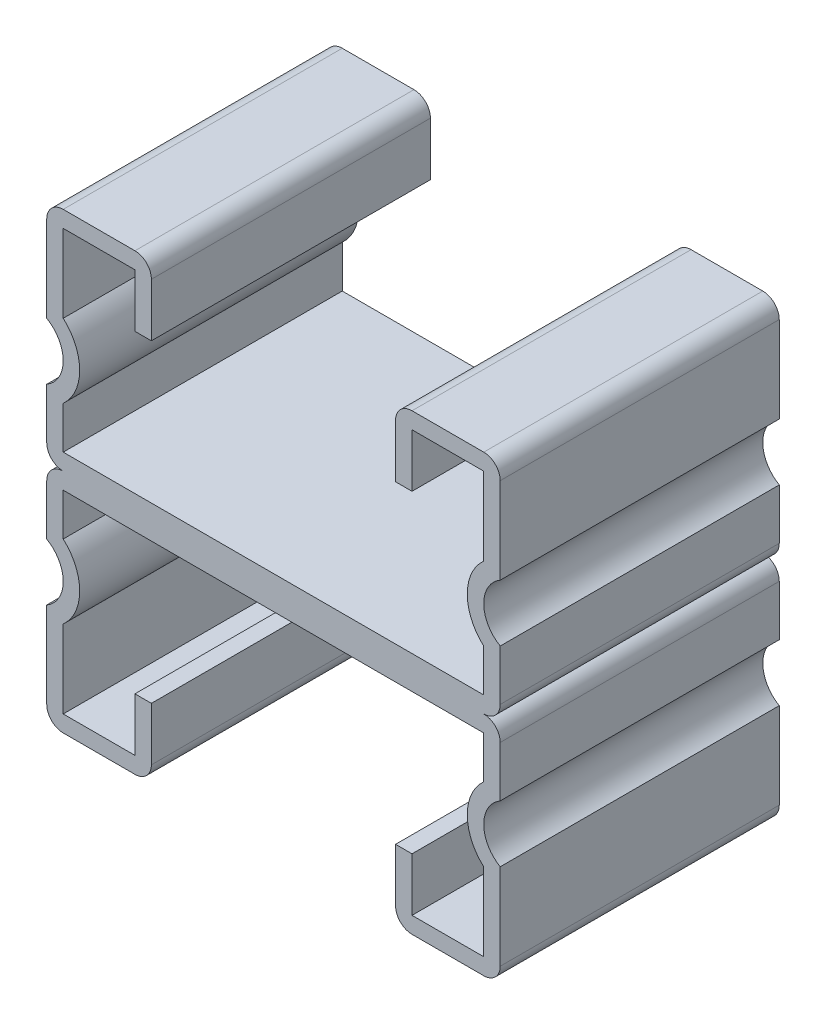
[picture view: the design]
ISO-10303-21;
HEADER;
FILE_DESCRIPTION(('STEP AP214'),'2;1');
FILE_NAME('part.step','',(''),(''),'','','');
FILE_SCHEMA(('AUTOMOTIVE_DESIGN { 1 0 10303 214 1 1 1 1 }'));
ENDSEC;
DATA;
#1=APPLICATION_CONTEXT('core data for automotive mechanical design processes');
#2=APPLICATION_PROTOCOL_DEFINITION('international standard','automotive_design',2000,#1);
#3=PRODUCT_CONTEXT('',#1,'mechanical');
#4=PRODUCT('Part','Part','',(#3));
#5=PRODUCT_RELATED_PRODUCT_CATEGORY('part','',(#4));
#6=PRODUCT_DEFINITION_FORMATION('','',#4);
#7=PRODUCT_DEFINITION_CONTEXT('part definition',#1,'design');
#8=PRODUCT_DEFINITION('design','',#6,#7);
#9=PRODUCT_DEFINITION_SHAPE('','',#8);
#10=(LENGTH_UNIT() NAMED_UNIT(*) SI_UNIT(.MILLI.,.METRE.));
#11=(NAMED_UNIT(*) PLANE_ANGLE_UNIT() SI_UNIT($,.RADIAN.));
#12=(NAMED_UNIT(*) SI_UNIT($,.STERADIAN.) SOLID_ANGLE_UNIT());
#13=UNCERTAINTY_MEASURE_WITH_UNIT(LENGTH_MEASURE(1.E-05),#10,'distance_accuracy_value','');
#14=(GEOMETRIC_REPRESENTATION_CONTEXT(3) GLOBAL_UNCERTAINTY_ASSIGNED_CONTEXT((#13)) GLOBAL_UNIT_ASSIGNED_CONTEXT((#10,
#11,#12)) REPRESENTATION_CONTEXT('',''));
#15=CARTESIAN_POINT('',(0.,0.,0.));
#16=DIRECTION('',(0.,0.,1.));
#17=DIRECTION('',(1.,0.,0.));
#18=AXIS2_PLACEMENT_3D('',#15,#16,#17);
#19=CARTESIAN_POINT('',(-19.1389,19.1389,12.7));
#20=DIRECTION('',(-1.,0.,0.));
#21=DIRECTION('',(0.,0.,1.));
#22=AXIS2_PLACEMENT_3D('',#19,#20,#21);
#23=PLANE('',#22);
#24=DIRECTION('',(0.,1.,0.));
#25=VECTOR('',#24,1.);
#26=CARTESIAN_POINT('',(-19.1389,19.1389,-12.7));
#27=LINE('',#26,#25);
#28=CARTESIAN_POINT('',(-19.1389,12.0504714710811,-12.7));
#29=VERTEX_POINT('',#28);
#30=CARTESIAN_POINT('',(-19.1389,19.1389,-12.7));
#31=VERTEX_POINT('',#30);
#32=EDGE_CURVE('E261',#29,#31,#27,.T.);
#33=ORIENTED_EDGE('',*,*,#32,.T.);
#34=DIRECTION('',(0.,0.,-1.));
#35=VECTOR('',#34,1.);
#36=CARTESIAN_POINT('',(-19.1389,19.1389,12.7));
#37=LINE('',#36,#35);
#38=CARTESIAN_POINT('',(-19.1389,19.1389,12.7));
#39=VERTEX_POINT('',#38);
#40=EDGE_CURVE('E11',#39,#31,#37,.T.);
#41=ORIENTED_EDGE('',*,*,#40,.F.);
#42=DIRECTION('',(0.,1.,0.));
#43=VECTOR('',#42,1.);
#44=CARTESIAN_POINT('',(-19.1389,19.1389,12.7));
#45=LINE('',#44,#43);
#46=CARTESIAN_POINT('',(-19.1389,12.0504714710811,12.7));
#47=VERTEX_POINT('',#46);
#48=EDGE_CURVE('E318',#47,#39,#45,.T.);
#49=ORIENTED_EDGE('',*,*,#48,.F.);
#50=DIRECTION('',(0.,0.,-1.));
#51=VECTOR('',#50,1.);
#52=CARTESIAN_POINT('',(-19.1389,12.0504714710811,12.7));
#53=LINE('',#52,#51);
#54=EDGE_CURVE('E257',#47,#29,#53,.T.);
#55=ORIENTED_EDGE('',*,*,#54,.T.);
#56=EDGE_LOOP('',(#33,#41,#49,#55));
#57=FACE_BOUND('',#56,.T.);
#58=ADVANCED_FACE('F32',(#57),#23,.F.);
#59=CARTESIAN_POINT('',(-19.1389,19.1389,12.7));
#60=DIRECTION('',(0.,1.,0.));
#61=DIRECTION('',(0.,0.,1.));
#62=AXIS2_PLACEMENT_3D('',#59,#60,#61);
#63=PLANE('',#62);
#64=DIRECTION('',(1.,0.,0.));
#65=VECTOR('',#64,1.);
#66=CARTESIAN_POINT('',(-19.1389,19.1389,-12.7));
#67=LINE('',#66,#65);
#68=CARTESIAN_POINT('',(-12.6111,19.1389,-12.7));
#69=VERTEX_POINT('',#68);
#70=EDGE_CURVE('E264',#31,#69,#67,.T.);
#71=ORIENTED_EDGE('',*,*,#70,.T.);
#72=DIRECTION('',(0.,0.,-1.));
#73=VECTOR('',#72,1.);
#74=CARTESIAN_POINT('',(-12.6111,19.1389,12.7));
#75=LINE('',#74,#73);
#76=CARTESIAN_POINT('',(-12.6111,19.1389,12.7));
#77=VERTEX_POINT('',#76);
#78=EDGE_CURVE('E40',#77,#69,#75,.T.);
#79=ORIENTED_EDGE('',*,*,#78,.F.);
#80=DIRECTION('',(1.,0.,0.));
#81=VECTOR('',#80,1.);
#82=CARTESIAN_POINT('',(-19.1389,19.1389,12.7));
#83=LINE('',#82,#81);
#84=EDGE_CURVE('E155',#39,#77,#83,.T.);
#85=ORIENTED_EDGE('',*,*,#84,.F.);
#86=ORIENTED_EDGE('',*,*,#40,.T.);
#87=EDGE_LOOP('',(#71,#79,#85,#86));
#88=FACE_BOUND('',#87,.T.);
#89=ADVANCED_FACE('F484',(#88),#63,.F.);
#90=CARTESIAN_POINT('',(-12.6111,19.1389,12.7));
#91=DIRECTION('',(1.,0.,0.));
#92=DIRECTION('',(0.,1.,0.));
#93=AXIS2_PLACEMENT_3D('',#90,#91,#92);
#94=PLANE('',#93);
#95=DIRECTION('',(0.,-1.,0.));
#96=VECTOR('',#95,1.);
#97=CARTESIAN_POINT('',(-12.6111,19.1389,-12.7));
#98=LINE('',#97,#96);
#99=CARTESIAN_POINT('',(-12.6111,14.2875,-12.7));
#100=VERTEX_POINT('',#99);
#101=EDGE_CURVE('E267',#69,#100,#98,.T.);
#102=ORIENTED_EDGE('',*,*,#101,.T.);
#103=DIRECTION('',(0.,0.,-1.));
#104=VECTOR('',#103,1.);
#105=CARTESIAN_POINT('',(-12.6111,14.2875,12.7));
#106=LINE('',#105,#104);
#107=CARTESIAN_POINT('',(-12.6111,14.2875,12.7));
#108=VERTEX_POINT('',#107);
#109=EDGE_CURVE('E391',#108,#100,#106,.T.);
#110=ORIENTED_EDGE('',*,*,#109,.F.);
#111=DIRECTION('',(0.,-1.,0.));
#112=VECTOR('',#111,1.);
#113=CARTESIAN_POINT('',(-12.6111,19.1389,12.7));
#114=LINE('',#113,#112);
#115=EDGE_CURVE('E399',#77,#108,#114,.T.);
#116=ORIENTED_EDGE('',*,*,#115,.F.);
#117=ORIENTED_EDGE('',*,*,#78,.T.);
#118=EDGE_LOOP('',(#102,#110,#116,#117));
#119=FACE_BOUND('',#118,.T.);
#120=ADVANCED_FACE('F397',(#119),#94,.F.);
#121=CARTESIAN_POINT('',(-12.6111,14.2875,12.7));
#122=DIRECTION('',(0.,1.,0.));
#123=DIRECTION('',(0.,0.,1.));
#124=AXIS2_PLACEMENT_3D('',#121,#122,#123);
#125=PLANE('',#124);
#126=DIRECTION('',(1.,0.,0.));
#127=VECTOR('',#126,1.);
#128=CARTESIAN_POINT('',(-12.6111,14.2875,-12.7));
#129=LINE('',#128,#127);
#130=CARTESIAN_POINT('',(-11.1125,14.2875,-12.7));
#131=VERTEX_POINT('',#130);
#132=EDGE_CURVE('E269',#100,#131,#129,.T.);
#133=ORIENTED_EDGE('',*,*,#132,.T.);
#134=DIRECTION('',(0.,0.,-1.));
#135=VECTOR('',#134,1.);
#136=CARTESIAN_POINT('',(-11.1125,14.2875,12.7));
#137=LINE('',#136,#135);
#138=CARTESIAN_POINT('',(-11.1125,14.2875,12.7));
#139=VERTEX_POINT('',#138);
#140=EDGE_CURVE('E388',#139,#131,#137,.T.);
#141=ORIENTED_EDGE('',*,*,#140,.F.);
#142=DIRECTION('',(1.,0.,0.));
#143=VECTOR('',#142,1.);
#144=CARTESIAN_POINT('',(-12.6111,14.2875,12.7));
#145=LINE('',#144,#143);
#146=EDGE_CURVE('E417',#108,#139,#145,.T.);
#147=ORIENTED_EDGE('',*,*,#146,.F.);
#148=ORIENTED_EDGE('',*,*,#109,.T.);
#149=EDGE_LOOP('',(#133,#141,#147,#148));
#150=FACE_BOUND('',#149,.T.);
#151=ADVANCED_FACE('F408',(#150),#125,.F.);
#152=CARTESIAN_POINT('',(-11.1125,19.1389,12.7));
#153=DIRECTION('',(-1.,0.,0.));
#154=DIRECTION('',(0.,-1.,0.));
#155=AXIS2_PLACEMENT_3D('',#152,#153,#154);
#156=PLANE('',#155);
#157=DIRECTION('',(0.,1.,0.));
#158=VECTOR('',#157,1.);
#159=CARTESIAN_POINT('',(-11.1125,19.1389,-12.7));
#160=LINE('',#159,#158);
#161=CARTESIAN_POINT('',(-11.1125,19.1389,-12.7));
#162=VERTEX_POINT('',#161);
#163=EDGE_CURVE('E271',#131,#162,#160,.T.);
#164=ORIENTED_EDGE('',*,*,#163,.T.);
#165=DIRECTION('',(0.,0.,-1.));
#166=VECTOR('',#165,1.);
#167=CARTESIAN_POINT('',(-11.1125,19.1389,12.7));
#168=LINE('',#167,#166);
#169=CARTESIAN_POINT('',(-11.1125,19.1389,12.7));
#170=VERTEX_POINT('',#169);
#171=EDGE_CURVE('E385',#170,#162,#168,.T.);
#172=ORIENTED_EDGE('',*,*,#171,.F.);
#173=DIRECTION('',(0.,1.,0.));
#174=VECTOR('',#173,1.);
#175=CARTESIAN_POINT('',(-11.1125,19.1389,12.7));
#176=LINE('',#175,#174);
#177=EDGE_CURVE('E414',#139,#170,#176,.T.);
#178=ORIENTED_EDGE('',*,*,#177,.F.);
#179=ORIENTED_EDGE('',*,*,#140,.T.);
#180=EDGE_LOOP('',(#164,#172,#178,#179));
#181=FACE_BOUND('',#180,.T.);
#182=ADVANCED_FACE('F412',(#181),#156,.F.);
#183=CARTESIAN_POINT('',(-12.6111,19.1389,12.7));
#184=DIRECTION('',(0.,0.,-1.));
#185=DIRECTION('',(-1.,0.,0.));
#186=AXIS2_PLACEMENT_3D('',#183,#184,#185);
#187=CYLINDRICAL_SURFACE('',#186,1.4986);
#188=CARTESIAN_POINT('',(-12.6111,19.1389,-12.7));
#189=DIRECTION('',(0.,0.,1.));
#190=DIRECTION('',(-1.,0.,0.));
#191=AXIS2_PLACEMENT_3D('',#188,#189,#190);
#192=CIRCLE('',#191,1.4986);
#193=CARTESIAN_POINT('',(-12.6111,20.6375,-12.7));
#194=VERTEX_POINT('',#193);
#195=EDGE_CURVE('E273',#162,#194,#192,.T.);
#196=ORIENTED_EDGE('',*,*,#195,.T.);
#197=DIRECTION('',(0.,0.,-1.));
#198=VECTOR('',#197,1.);
#199=CARTESIAN_POINT('',(-12.6111,20.6375,12.7));
#200=LINE('',#199,#198);
#201=CARTESIAN_POINT('',(-12.6111,20.6375,12.7));
#202=VERTEX_POINT('',#201);
#203=EDGE_CURVE('E382',#202,#194,#200,.T.);
#204=ORIENTED_EDGE('',*,*,#203,.F.);
#205=CARTESIAN_POINT('',(-12.6111,19.1389,12.7));
#206=DIRECTION('',(0.,0.,1.));
#207=DIRECTION('',(-1.,0.,0.));
#208=AXIS2_PLACEMENT_3D('',#205,#206,#207);
#209=CIRCLE('',#208,1.4986);
#210=EDGE_CURVE('E416',#170,#202,#209,.T.);
#211=ORIENTED_EDGE('',*,*,#210,.F.);
#212=ORIENTED_EDGE('',*,*,#171,.T.);
#213=EDGE_LOOP('',(#196,#204,#211,#212));
#214=FACE_BOUND('',#213,.T.);
#215=ADVANCED_FACE('F497',(#214),#187,.T.);
#216=CARTESIAN_POINT('',(-19.1389,20.6375,12.7));
#217=DIRECTION('',(0.,-1.,0.));
#218=DIRECTION('',(0.,0.,-1.));
#219=AXIS2_PLACEMENT_3D('',#216,#217,#218);
#220=PLANE('',#219);
#221=DIRECTION('',(-1.,0.,0.));
#222=VECTOR('',#221,1.);
#223=CARTESIAN_POINT('',(-19.1389,20.6375,-12.7));
#224=LINE('',#223,#222);
#225=CARTESIAN_POINT('',(-19.1389,20.6375,-12.7));
#226=VERTEX_POINT('',#225);
#227=EDGE_CURVE('E275',#194,#226,#224,.T.);
#228=ORIENTED_EDGE('',*,*,#227,.T.);
#229=DIRECTION('',(0.,0.,-1.));
#230=VECTOR('',#229,1.);
#231=CARTESIAN_POINT('',(-19.1389,20.6375,12.7));
#232=LINE('',#231,#230);
#233=CARTESIAN_POINT('',(-19.1389,20.6375,12.7));
#234=VERTEX_POINT('',#233);
#235=EDGE_CURVE('E379',#234,#226,#232,.T.);
#236=ORIENTED_EDGE('',*,*,#235,.F.);
#237=DIRECTION('',(-1.,0.,0.));
#238=VECTOR('',#237,1.);
#239=CARTESIAN_POINT('',(-19.1389,20.6375,12.7));
#240=LINE('',#239,#238);
#241=EDGE_CURVE('E419',#202,#234,#240,.T.);
#242=ORIENTED_EDGE('',*,*,#241,.F.);
#243=ORIENTED_EDGE('',*,*,#203,.T.);
#244=EDGE_LOOP('',(#228,#236,#242,#243));
#245=FACE_BOUND('',#244,.T.);
#246=ADVANCED_FACE('F500',(#245),#220,.F.);
#247=CARTESIAN_POINT('',(-19.1389,19.1389,12.7));
#248=DIRECTION('',(0.,0.,-1.));
#249=DIRECTION('',(-1.,0.,0.));
#250=AXIS2_PLACEMENT_3D('',#247,#248,#249);
#251=CYLINDRICAL_SURFACE('',#250,1.4986);
#252=CARTESIAN_POINT('',(-19.1389,19.1389,-12.7));
#253=DIRECTION('',(0.,0.,1.));
#254=DIRECTION('',(-1.,0.,0.));
#255=AXIS2_PLACEMENT_3D('',#252,#253,#254);
#256=CIRCLE('',#255,1.4986);
#257=CARTESIAN_POINT('',(-20.6375,19.1389,-12.7));
#258=VERTEX_POINT('',#257);
#259=EDGE_CURVE('E277',#226,#258,#256,.T.);
#260=ORIENTED_EDGE('',*,*,#259,.T.);
#261=DIRECTION('',(0.,0.,-1.));
#262=VECTOR('',#261,1.);
#263=CARTESIAN_POINT('',(-20.6375,19.1389,12.7));
#264=LINE('',#263,#262);
#265=CARTESIAN_POINT('',(-20.6375,19.1389,12.7));
#266=VERTEX_POINT('',#265);
#267=EDGE_CURVE('E376',#266,#258,#264,.T.);
#268=ORIENTED_EDGE('',*,*,#267,.F.);
#269=CARTESIAN_POINT('',(-19.1389,19.1389,12.7));
#270=DIRECTION('',(0.,0.,1.));
#271=DIRECTION('',(-1.,0.,0.));
#272=AXIS2_PLACEMENT_3D('',#269,#270,#271);
#273=CIRCLE('',#272,1.4986);
#274=EDGE_CURVE('E425',#234,#266,#273,.T.);
#275=ORIENTED_EDGE('',*,*,#274,.F.);
#276=ORIENTED_EDGE('',*,*,#235,.T.);
#277=EDGE_LOOP('',(#260,#268,#275,#276));
#278=FACE_BOUND('',#277,.T.);
#279=ADVANCED_FACE('F504',(#278),#251,.T.);
#280=CARTESIAN_POINT('',(-20.6375,19.1389,12.7));
#281=DIRECTION('',(1.,0.,0.));
#282=DIRECTION('',(0.,1.,0.));
#283=AXIS2_PLACEMENT_3D('',#280,#281,#282);
#284=PLANE('',#283);
#285=DIRECTION('',(0.,-1.,0.));
#286=VECTOR('',#285,1.);
#287=CARTESIAN_POINT('',(-20.6375,19.1389,-12.7));
#288=LINE('',#287,#286);
#289=CARTESIAN_POINT('',(-20.6375,11.2951513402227,-12.7));
#290=VERTEX_POINT('',#289);
#291=EDGE_CURVE('E279',#258,#290,#288,.T.);
#292=ORIENTED_EDGE('',*,*,#291,.T.);
#293=DIRECTION('',(0.,0.,-1.));
#294=VECTOR('',#293,1.);
#295=CARTESIAN_POINT('',(-20.6375,11.2951513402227,12.7));
#296=LINE('',#295,#294);
#297=CARTESIAN_POINT('',(-20.6375,11.2951513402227,12.7));
#298=VERTEX_POINT('',#297);
#299=EDGE_CURVE('E373',#298,#290,#296,.T.);
#300=ORIENTED_EDGE('',*,*,#299,.F.);
#301=DIRECTION('',(0.,-1.,0.));
#302=VECTOR('',#301,1.);
#303=CARTESIAN_POINT('',(-20.6375,19.1389,12.7));
#304=LINE('',#303,#302);
#305=EDGE_CURVE('E427',#266,#298,#304,.T.);
#306=ORIENTED_EDGE('',*,*,#305,.F.);
#307=ORIENTED_EDGE('',*,*,#267,.T.);
#308=EDGE_LOOP('',(#292,#300,#306,#307));
#309=FACE_BOUND('',#308,.T.);
#310=ADVANCED_FACE('F508',(#309),#284,.F.);
#311=CARTESIAN_POINT('',(-22.1361,8.69949999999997,12.7));
#312=DIRECTION('',(0.,0.,-1.));
#313=DIRECTION('',(-1.,0.,0.));
#314=AXIS2_PLACEMENT_3D('',#311,#312,#313);
#315=CYLINDRICAL_SURFACE('',#314,2.9972);
#316=CARTESIAN_POINT('',(-22.1361,8.69949999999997,-12.7));
#317=DIRECTION('',(0.,0.,-1.));
#318=DIRECTION('',(1.,0.,0.));
#319=AXIS2_PLACEMENT_3D('',#316,#317,#318);
#320=CIRCLE('',#319,2.9972);
#321=CARTESIAN_POINT('',(-20.6375,6.10384865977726,-12.7));
#322=VERTEX_POINT('',#321);
#323=EDGE_CURVE('E281',#290,#322,#320,.T.);
#324=ORIENTED_EDGE('',*,*,#323,.T.);
#325=DIRECTION('',(0.,0.,-1.));
#326=VECTOR('',#325,1.);
#327=CARTESIAN_POINT('',(-20.6375,6.10384865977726,12.7));
#328=LINE('',#327,#326);
#329=CARTESIAN_POINT('',(-20.6375,6.10384865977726,12.7));
#330=VERTEX_POINT('',#329);
#331=EDGE_CURVE('E370',#330,#322,#328,.T.);
#332=ORIENTED_EDGE('',*,*,#331,.F.);
#333=CARTESIAN_POINT('',(-22.1361,8.69949999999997,12.7));
#334=DIRECTION('',(0.,0.,-1.));
#335=DIRECTION('',(1.,0.,0.));
#336=AXIS2_PLACEMENT_3D('',#333,#334,#335);
#337=CIRCLE('',#336,2.9972);
#338=EDGE_CURVE('E429',#298,#330,#337,.T.);
#339=ORIENTED_EDGE('',*,*,#338,.F.);
#340=ORIENTED_EDGE('',*,*,#299,.T.);
#341=EDGE_LOOP('',(#324,#332,#339,#340));
#342=FACE_BOUND('',#341,.T.);
#343=ADVANCED_FACE('F512',(#342),#315,.F.);
#344=CARTESIAN_POINT('',(-20.6375,6.10384865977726,12.7));
#345=DIRECTION('',(1.,0.,0.));
#346=DIRECTION('',(0.,0.,-1.));
#347=AXIS2_PLACEMENT_3D('',#344,#345,#346);
#348=PLANE('',#347);
#349=DIRECTION('',(0.,-1.,0.));
#350=VECTOR('',#349,1.);
#351=CARTESIAN_POINT('',(-20.6375,6.10384865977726,-12.7));
#352=LINE('',#351,#350);
#353=CARTESIAN_POINT('',(-20.6375,1.4986,-12.7));
#354=VERTEX_POINT('',#353);
#355=EDGE_CURVE('E283',#322,#354,#352,.T.);
#356=ORIENTED_EDGE('',*,*,#355,.T.);
#357=DIRECTION('',(0.,0.,-1.));
#358=VECTOR('',#357,1.);
#359=CARTESIAN_POINT('',(-20.6375,1.4986,12.7));
#360=LINE('',#359,#358);
#361=CARTESIAN_POINT('',(-20.6375,1.4986,12.7));
#362=VERTEX_POINT('',#361);
#363=EDGE_CURVE('E367',#362,#354,#360,.T.);
#364=ORIENTED_EDGE('',*,*,#363,.F.);
#365=DIRECTION('',(0.,-1.,0.));
#366=VECTOR('',#365,1.);
#367=CARTESIAN_POINT('',(-20.6375,6.10384865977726,12.7));
#368=LINE('',#367,#366);
#369=EDGE_CURVE('E431',#330,#362,#368,.T.);
#370=ORIENTED_EDGE('',*,*,#369,.F.);
#371=ORIENTED_EDGE('',*,*,#331,.T.);
#372=EDGE_LOOP('',(#356,#364,#370,#371));
#373=FACE_BOUND('',#372,.T.);
#374=ADVANCED_FACE('F516',(#373),#348,.F.);
#375=CARTESIAN_POINT('',(-19.1389,1.4986,12.7));
#376=DIRECTION('',(0.,0.,-1.));
#377=DIRECTION('',(-1.,0.,0.));
#378=AXIS2_PLACEMENT_3D('',#375,#376,#377);
#379=CYLINDRICAL_SURFACE('',#378,1.4986);
#380=CARTESIAN_POINT('',(-19.1389,1.4986,-12.7));
#381=DIRECTION('',(0.,0.,1.));
#382=DIRECTION('',(-1.,0.,0.));
#383=AXIS2_PLACEMENT_3D('',#380,#381,#382);
#384=CIRCLE('',#383,1.4986);
#385=CARTESIAN_POINT('',(-19.1389,0.,-12.7));
#386=VERTEX_POINT('',#385);
#387=EDGE_CURVE('E285',#354,#386,#384,.T.);
#388=ORIENTED_EDGE('',*,*,#387,.T.);
#389=DIRECTION('',(0.,0.,-1.));
#390=VECTOR('',#389,1.);
#391=CARTESIAN_POINT('',(-19.1389,0.,12.7));
#392=LINE('',#391,#390);
#393=CARTESIAN_POINT('',(-19.1389,0.,12.7));
#394=VERTEX_POINT('',#393);
#395=EDGE_CURVE('E364',#394,#386,#392,.T.);
#396=ORIENTED_EDGE('',*,*,#395,.F.);
#397=CARTESIAN_POINT('',(-19.1389,1.4986,12.7));
#398=DIRECTION('',(0.,0.,1.));
#399=DIRECTION('',(-1.,0.,0.));
#400=AXIS2_PLACEMENT_3D('',#397,#398,#399);
#401=CIRCLE('',#400,1.4986);
#402=EDGE_CURVE('E433',#362,#394,#401,.T.);
#403=ORIENTED_EDGE('',*,*,#402,.F.);
#404=ORIENTED_EDGE('',*,*,#363,.T.);
#405=EDGE_LOOP('',(#388,#396,#403,#404));
#406=FACE_BOUND('',#405,.T.);
#407=ADVANCED_FACE('F520',(#406),#379,.T.);
#408=CARTESIAN_POINT('',(19.1389,1.49860000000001,12.7));
#409=DIRECTION('',(0.,0.,-1.));
#410=DIRECTION('',(-1.,0.,0.));
#411=AXIS2_PLACEMENT_3D('',#408,#409,#410);
#412=CYLINDRICAL_SURFACE('',#411,1.4986);
#413=CARTESIAN_POINT('',(19.1389,1.49860000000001,-12.7));
#414=DIRECTION('',(0.,0.,1.));
#415=DIRECTION('',(-1.,0.,0.));
#416=AXIS2_PLACEMENT_3D('',#413,#414,#415);
#417=CIRCLE('',#416,1.4986);
#418=CARTESIAN_POINT('',(19.1389,0.,-12.7));
#419=VERTEX_POINT('',#418);
#420=CARTESIAN_POINT('',(20.6375,1.49860000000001,-12.7));
#421=VERTEX_POINT('',#420);
#422=EDGE_CURVE('E287',#419,#421,#417,.T.);
#423=ORIENTED_EDGE('',*,*,#422,.T.);
#424=DIRECTION('',(0.,0.,-1.));
#425=VECTOR('',#424,1.);
#426=CARTESIAN_POINT('',(20.6375,1.49860000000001,12.7));
#427=LINE('',#426,#425);
#428=CARTESIAN_POINT('',(20.6375,1.49860000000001,12.7));
#429=VERTEX_POINT('',#428);
#430=EDGE_CURVE('E358',#429,#421,#427,.T.);
#431=ORIENTED_EDGE('',*,*,#430,.F.);
#432=CARTESIAN_POINT('',(19.1389,1.49860000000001,12.7));
#433=DIRECTION('',(0.,0.,1.));
#434=DIRECTION('',(-1.,0.,0.));
#435=AXIS2_PLACEMENT_3D('',#432,#433,#434);
#436=CIRCLE('',#435,1.4986);
#437=CARTESIAN_POINT('',(19.1389,0.,12.7));
#438=VERTEX_POINT('',#437);
#439=EDGE_CURVE('E435',#438,#429,#436,.T.);
#440=ORIENTED_EDGE('',*,*,#439,.F.);
#441=DIRECTION('',(0.,0.,-1.));
#442=VECTOR('',#441,1.);
#443=CARTESIAN_POINT('',(19.1389,0.,12.7));
#444=LINE('',#443,#442);
#445=EDGE_CURVE('E361',#438,#419,#444,.T.);
#446=ORIENTED_EDGE('',*,*,#445,.T.);
#447=EDGE_LOOP('',(#423,#431,#440,#446));
#448=FACE_BOUND('',#447,.T.);
#449=ADVANCED_FACE('F524',(#448),#412,.T.);
#450=CARTESIAN_POINT('',(20.6375,1.49860000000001,12.7));
#451=DIRECTION('',(-1.,0.,0.));
#452=DIRECTION('',(0.,0.,1.));
#453=AXIS2_PLACEMENT_3D('',#450,#451,#452);
#454=PLANE('',#453);
#455=DIRECTION('',(0.,1.,0.));
#456=VECTOR('',#455,1.);
#457=CARTESIAN_POINT('',(20.6375,1.49860000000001,-12.7));
#458=LINE('',#457,#456);
#459=CARTESIAN_POINT('',(20.6375,6.10384865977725,-12.7));
#460=VERTEX_POINT('',#459);
#461=EDGE_CURVE('E289',#421,#460,#458,.T.);
#462=ORIENTED_EDGE('',*,*,#461,.T.);
#463=DIRECTION('',(0.,0.,-1.));
#464=VECTOR('',#463,1.);
#465=CARTESIAN_POINT('',(20.6375,6.10384865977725,12.7));
#466=LINE('',#465,#464);
#467=CARTESIAN_POINT('',(20.6375,6.10384865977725,12.7));
#468=VERTEX_POINT('',#467);
#469=EDGE_CURVE('E355',#468,#460,#466,.T.);
#470=ORIENTED_EDGE('',*,*,#469,.F.);
#471=DIRECTION('',(0.,1.,0.));
#472=VECTOR('',#471,1.);
#473=CARTESIAN_POINT('',(20.6375,1.49860000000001,12.7));
#474=LINE('',#473,#472);
#475=EDGE_CURVE('E437',#429,#468,#474,.T.);
#476=ORIENTED_EDGE('',*,*,#475,.F.);
#477=ORIENTED_EDGE('',*,*,#430,.T.);
#478=EDGE_LOOP('',(#462,#470,#476,#477));
#479=FACE_BOUND('',#478,.T.);
#480=ADVANCED_FACE('F528',(#479),#454,.F.);
#481=CARTESIAN_POINT('',(22.1361,8.69949999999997,12.7));
#482=DIRECTION('',(0.,0.,-1.));
#483=DIRECTION('',(-1.,0.,0.));
#484=AXIS2_PLACEMENT_3D('',#481,#482,#483);
#485=CYLINDRICAL_SURFACE('',#484,2.9972);
#486=CARTESIAN_POINT('',(22.1361,8.69949999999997,-12.7));
#487=DIRECTION('',(0.,0.,-1.));
#488=DIRECTION('',(1.,0.,0.));
#489=AXIS2_PLACEMENT_3D('',#486,#487,#488);
#490=CIRCLE('',#489,2.9972);
#491=CARTESIAN_POINT('',(20.6375,11.2951513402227,-12.7));
#492=VERTEX_POINT('',#491);
#493=EDGE_CURVE('E291',#460,#492,#490,.T.);
#494=ORIENTED_EDGE('',*,*,#493,.T.);
#495=DIRECTION('',(0.,0.,-1.));
#496=VECTOR('',#495,1.);
#497=CARTESIAN_POINT('',(20.6375,11.2951513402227,12.7));
#498=LINE('',#497,#496);
#499=CARTESIAN_POINT('',(20.6375,11.2951513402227,12.7));
#500=VERTEX_POINT('',#499);
#501=EDGE_CURVE('E352',#500,#492,#498,.T.);
#502=ORIENTED_EDGE('',*,*,#501,.F.);
#503=CARTESIAN_POINT('',(22.1361,8.69949999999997,12.7));
#504=DIRECTION('',(0.,0.,-1.));
#505=DIRECTION('',(1.,0.,0.));
#506=AXIS2_PLACEMENT_3D('',#503,#504,#505);
#507=CIRCLE('',#506,2.9972);
#508=EDGE_CURVE('E439',#468,#500,#507,.T.);
#509=ORIENTED_EDGE('',*,*,#508,.F.);
#510=ORIENTED_EDGE('',*,*,#469,.T.);
#511=EDGE_LOOP('',(#494,#502,#509,#510));
#512=FACE_BOUND('',#511,.T.);
#513=ADVANCED_FACE('F532',(#512),#485,.F.);
#514=CARTESIAN_POINT('',(20.6375,11.2951513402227,12.7));
#515=DIRECTION('',(-1.,0.,0.));
#516=DIRECTION('',(0.,-1.,0.));
#517=AXIS2_PLACEMENT_3D('',#514,#515,#516);
#518=PLANE('',#517);
#519=DIRECTION('',(0.,1.,0.));
#520=VECTOR('',#519,1.);
#521=CARTESIAN_POINT('',(20.6375,11.2951513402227,-12.7));
#522=LINE('',#521,#520);
#523=CARTESIAN_POINT('',(20.6375,19.1389,-12.7));
#524=VERTEX_POINT('',#523);
#525=EDGE_CURVE('E293',#492,#524,#522,.T.);
#526=ORIENTED_EDGE('',*,*,#525,.T.);
#527=DIRECTION('',(0.,0.,-1.));
#528=VECTOR('',#527,1.);
#529=CARTESIAN_POINT('',(20.6375,19.1389,12.7));
#530=LINE('',#529,#528);
#531=CARTESIAN_POINT('',(20.6375,19.1389,12.7));
#532=VERTEX_POINT('',#531);
#533=EDGE_CURVE('E349',#532,#524,#530,.T.);
#534=ORIENTED_EDGE('',*,*,#533,.F.);
#535=DIRECTION('',(0.,1.,0.));
#536=VECTOR('',#535,1.);
#537=CARTESIAN_POINT('',(20.6375,11.2951513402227,12.7));
#538=LINE('',#537,#536);
#539=EDGE_CURVE('E441',#500,#532,#538,.T.);
#540=ORIENTED_EDGE('',*,*,#539,.F.);
#541=ORIENTED_EDGE('',*,*,#501,.T.);
#542=EDGE_LOOP('',(#526,#534,#540,#541));
#543=FACE_BOUND('',#542,.T.);
#544=ADVANCED_FACE('F536',(#543),#518,.F.);
#545=CARTESIAN_POINT('',(19.1389,19.1389,12.7));
#546=DIRECTION('',(0.,0.,-1.));
#547=DIRECTION('',(-1.,0.,0.));
#548=AXIS2_PLACEMENT_3D('',#545,#546,#547);
#549=CYLINDRICAL_SURFACE('',#548,1.4986);
#550=CARTESIAN_POINT('',(19.1389,19.1389,-12.7));
#551=DIRECTION('',(0.,0.,1.));
#552=DIRECTION('',(-1.,0.,0.));
#553=AXIS2_PLACEMENT_3D('',#550,#551,#552);
#554=CIRCLE('',#553,1.4986);
#555=CARTESIAN_POINT('',(19.1389,20.6375,-12.7));
#556=VERTEX_POINT('',#555);
#557=EDGE_CURVE('E295',#524,#556,#554,.T.);
#558=ORIENTED_EDGE('',*,*,#557,.T.);
#559=DIRECTION('',(0.,0.,-1.));
#560=VECTOR('',#559,1.);
#561=CARTESIAN_POINT('',(19.1389,20.6375,12.7));
#562=LINE('',#561,#560);
#563=CARTESIAN_POINT('',(19.1389,20.6375,12.7));
#564=VERTEX_POINT('',#563);
#565=EDGE_CURVE('E346',#564,#556,#562,.T.);
#566=ORIENTED_EDGE('',*,*,#565,.F.);
#567=CARTESIAN_POINT('',(19.1389,19.1389,12.7));
#568=DIRECTION('',(0.,0.,1.));
#569=DIRECTION('',(-1.,0.,0.));
#570=AXIS2_PLACEMENT_3D('',#567,#568,#569);
#571=CIRCLE('',#570,1.4986);
#572=EDGE_CURVE('E443',#532,#564,#571,.T.);
#573=ORIENTED_EDGE('',*,*,#572,.F.);
#574=ORIENTED_EDGE('',*,*,#533,.T.);
#575=EDGE_LOOP('',(#558,#566,#573,#574));
#576=FACE_BOUND('',#575,.T.);
#577=ADVANCED_FACE('F540',(#576),#549,.T.);
#578=CARTESIAN_POINT('',(19.1389,20.6375,12.7));
#579=DIRECTION('',(0.,-1.,0.));
#580=DIRECTION('',(1.,0.,0.));
#581=AXIS2_PLACEMENT_3D('',#578,#579,#580);
#582=PLANE('',#581);
#583=DIRECTION('',(-1.,0.,0.));
#584=VECTOR('',#583,1.);
#585=CARTESIAN_POINT('',(19.1389,20.6375,-12.7));
#586=LINE('',#585,#584);
#587=CARTESIAN_POINT('',(12.6111,20.6375,-12.7));
#588=VERTEX_POINT('',#587);
#589=EDGE_CURVE('E297',#556,#588,#586,.T.);
#590=ORIENTED_EDGE('',*,*,#589,.T.);
#591=DIRECTION('',(0.,0.,-1.));
#592=VECTOR('',#591,1.);
#593=CARTESIAN_POINT('',(12.6111,20.6375,12.7));
#594=LINE('',#593,#592);
#595=CARTESIAN_POINT('',(12.6111,20.6375,12.7));
#596=VERTEX_POINT('',#595);
#597=EDGE_CURVE('E343',#596,#588,#594,.T.);
#598=ORIENTED_EDGE('',*,*,#597,.F.);
#599=DIRECTION('',(-1.,0.,0.));
#600=VECTOR('',#599,1.);
#601=CARTESIAN_POINT('',(19.1389,20.6375,12.7));
#602=LINE('',#601,#600);
#603=EDGE_CURVE('E445',#564,#596,#602,.T.);
#604=ORIENTED_EDGE('',*,*,#603,.F.);
#605=ORIENTED_EDGE('',*,*,#565,.T.);
#606=EDGE_LOOP('',(#590,#598,#604,#605));
#607=FACE_BOUND('',#606,.T.);
#608=ADVANCED_FACE('F544',(#607),#582,.F.);
#609=CARTESIAN_POINT('',(12.6111,19.1389,12.7));
#610=DIRECTION('',(0.,0.,-1.));
#611=DIRECTION('',(-1.,0.,0.));
#612=AXIS2_PLACEMENT_3D('',#609,#610,#611);
#613=CYLINDRICAL_SURFACE('',#612,1.4986);
#614=CARTESIAN_POINT('',(12.6111,19.1389,-12.7));
#615=DIRECTION('',(0.,0.,1.));
#616=DIRECTION('',(-1.,0.,0.));
#617=AXIS2_PLACEMENT_3D('',#614,#615,#616);
#618=CIRCLE('',#617,1.4986);
#619=CARTESIAN_POINT('',(11.1125,19.1389,-12.7));
#620=VERTEX_POINT('',#619);
#621=EDGE_CURVE('E299',#588,#620,#618,.T.);
#622=ORIENTED_EDGE('',*,*,#621,.T.);
#623=DIRECTION('',(0.,0.,-1.));
#624=VECTOR('',#623,1.);
#625=CARTESIAN_POINT('',(11.1125,19.1389,12.7));
#626=LINE('',#625,#624);
#627=CARTESIAN_POINT('',(11.1125,19.1389,12.7));
#628=VERTEX_POINT('',#627);
#629=EDGE_CURVE('E340',#628,#620,#626,.T.);
#630=ORIENTED_EDGE('',*,*,#629,.F.);
#631=CARTESIAN_POINT('',(12.6111,19.1389,12.7));
#632=DIRECTION('',(0.,0.,1.));
#633=DIRECTION('',(-1.,0.,0.));
#634=AXIS2_PLACEMENT_3D('',#631,#632,#633);
#635=CIRCLE('',#634,1.4986);
#636=EDGE_CURVE('E447',#596,#628,#635,.T.);
#637=ORIENTED_EDGE('',*,*,#636,.F.);
#638=ORIENTED_EDGE('',*,*,#597,.T.);
#639=EDGE_LOOP('',(#622,#630,#637,#638));
#640=FACE_BOUND('',#639,.T.);
#641=ADVANCED_FACE('F548',(#640),#613,.T.);
#642=CARTESIAN_POINT('',(11.1125,19.1389,12.7));
#643=DIRECTION('',(1.,0.,0.));
#644=DIRECTION('',(0.,1.,0.));
#645=AXIS2_PLACEMENT_3D('',#642,#643,#644);
#646=PLANE('',#645);
#647=DIRECTION('',(0.,-1.,0.));
#648=VECTOR('',#647,1.);
#649=CARTESIAN_POINT('',(11.1125,19.1389,-12.7));
#650=LINE('',#649,#648);
#651=CARTESIAN_POINT('',(11.1125,14.2875,-12.7));
#652=VERTEX_POINT('',#651);
#653=EDGE_CURVE('E301',#620,#652,#650,.T.);
#654=ORIENTED_EDGE('',*,*,#653,.T.);
#655=DIRECTION('',(0.,0.,-1.));
#656=VECTOR('',#655,1.);
#657=CARTESIAN_POINT('',(11.1125,14.2875,12.7));
#658=LINE('',#657,#656);
#659=CARTESIAN_POINT('',(11.1125,14.2875,12.7));
#660=VERTEX_POINT('',#659);
#661=EDGE_CURVE('E337',#660,#652,#658,.T.);
#662=ORIENTED_EDGE('',*,*,#661,.F.);
#663=DIRECTION('',(0.,-1.,0.));
#664=VECTOR('',#663,1.);
#665=CARTESIAN_POINT('',(11.1125,19.1389,12.7));
#666=LINE('',#665,#664);
#667=EDGE_CURVE('E449',#628,#660,#666,.T.);
#668=ORIENTED_EDGE('',*,*,#667,.F.);
#669=ORIENTED_EDGE('',*,*,#629,.T.);
#670=EDGE_LOOP('',(#654,#662,#668,#669));
#671=FACE_BOUND('',#670,.T.);
#672=ADVANCED_FACE('F552',(#671),#646,.F.);
#673=CARTESIAN_POINT('',(11.1125,14.2875,12.7));
#674=DIRECTION('',(0.,1.,0.));
#675=DIRECTION('',(0.,0.,1.));
#676=AXIS2_PLACEMENT_3D('',#673,#674,#675);
#677=PLANE('',#676);
#678=DIRECTION('',(1.,0.,0.));
#679=VECTOR('',#678,1.);
#680=CARTESIAN_POINT('',(11.1125,14.2875,-12.7));
#681=LINE('',#680,#679);
#682=CARTESIAN_POINT('',(12.6111,14.2875,-12.7));
#683=VERTEX_POINT('',#682);
#684=EDGE_CURVE('E303',#652,#683,#681,.T.);
#685=ORIENTED_EDGE('',*,*,#684,.T.);
#686=DIRECTION('',(0.,0.,-1.));
#687=VECTOR('',#686,1.);
#688=CARTESIAN_POINT('',(12.6111,14.2875,12.7));
#689=LINE('',#688,#687);
#690=CARTESIAN_POINT('',(12.6111,14.2875,12.7));
#691=VERTEX_POINT('',#690);
#692=EDGE_CURVE('E334',#691,#683,#689,.T.);
#693=ORIENTED_EDGE('',*,*,#692,.F.);
#694=DIRECTION('',(1.,0.,0.));
#695=VECTOR('',#694,1.);
#696=CARTESIAN_POINT('',(11.1125,14.2875,12.7));
#697=LINE('',#696,#695);
#698=EDGE_CURVE('E451',#660,#691,#697,.T.);
#699=ORIENTED_EDGE('',*,*,#698,.F.);
#700=ORIENTED_EDGE('',*,*,#661,.T.);
#701=EDGE_LOOP('',(#685,#693,#699,#700));
#702=FACE_BOUND('',#701,.T.);
#703=ADVANCED_FACE('F556',(#702),#677,.F.);
#704=CARTESIAN_POINT('',(12.6111,19.1389,12.7));
#705=DIRECTION('',(-1.,0.,0.));
#706=DIRECTION('',(0.,0.,1.));
#707=AXIS2_PLACEMENT_3D('',#704,#705,#706);
#708=PLANE('',#707);
#709=DIRECTION('',(0.,1.,0.));
#710=VECTOR('',#709,1.);
#711=CARTESIAN_POINT('',(12.6111,19.1389,-12.7));
#712=LINE('',#711,#710);
#713=CARTESIAN_POINT('',(12.6111,19.1389,-12.7));
#714=VERTEX_POINT('',#713);
#715=EDGE_CURVE('E305',#683,#714,#712,.T.);
#716=ORIENTED_EDGE('',*,*,#715,.T.);
#717=DIRECTION('',(0.,0.,-1.));
#718=VECTOR('',#717,1.);
#719=CARTESIAN_POINT('',(12.6111,19.1389,12.7));
#720=LINE('',#719,#718);
#721=CARTESIAN_POINT('',(12.6111,19.1389,12.7));
#722=VERTEX_POINT('',#721);
#723=EDGE_CURVE('E331',#722,#714,#720,.T.);
#724=ORIENTED_EDGE('',*,*,#723,.F.);
#725=DIRECTION('',(0.,1.,0.));
#726=VECTOR('',#725,1.);
#727=CARTESIAN_POINT('',(12.6111,19.1389,12.7));
#728=LINE('',#727,#726);
#729=EDGE_CURVE('E453',#691,#722,#728,.T.);
#730=ORIENTED_EDGE('',*,*,#729,.F.);
#731=ORIENTED_EDGE('',*,*,#692,.T.);
#732=EDGE_LOOP('',(#716,#724,#730,#731));
#733=FACE_BOUND('',#732,.T.);
#734=ADVANCED_FACE('F560',(#733),#708,.F.);
#735=CARTESIAN_POINT('',(19.1389,19.1389,12.7));
#736=DIRECTION('',(0.,1.,0.));
#737=DIRECTION('',(-1.,0.,0.));
#738=AXIS2_PLACEMENT_3D('',#735,#736,#737);
#739=PLANE('',#738);
#740=DIRECTION('',(1.,0.,0.));
#741=VECTOR('',#740,1.);
#742=CARTESIAN_POINT('',(19.1389,19.1389,-12.7));
#743=LINE('',#742,#741);
#744=CARTESIAN_POINT('',(19.1389,19.1389,-12.7));
#745=VERTEX_POINT('',#744);
#746=EDGE_CURVE('E307',#714,#745,#743,.T.);
#747=ORIENTED_EDGE('',*,*,#746,.T.);
#748=DIRECTION('',(0.,0.,-1.));
#749=VECTOR('',#748,1.);
#750=CARTESIAN_POINT('',(19.1389,19.1389,12.7));
#751=LINE('',#750,#749);
#752=CARTESIAN_POINT('',(19.1389,19.1389,12.7));
#753=VERTEX_POINT('',#752);
#754=EDGE_CURVE('E328',#753,#745,#751,.T.);
#755=ORIENTED_EDGE('',*,*,#754,.F.);
#756=DIRECTION('',(1.,0.,0.));
#757=VECTOR('',#756,1.);
#758=CARTESIAN_POINT('',(19.1389,19.1389,12.7));
#759=LINE('',#758,#757);
#760=EDGE_CURVE('E455',#722,#753,#759,.T.);
#761=ORIENTED_EDGE('',*,*,#760,.F.);
#762=ORIENTED_EDGE('',*,*,#723,.T.);
#763=EDGE_LOOP('',(#747,#755,#761,#762));
#764=FACE_BOUND('',#763,.T.);
#765=ADVANCED_FACE('F564',(#764),#739,.F.);
#766=CARTESIAN_POINT('',(19.1389,12.0504714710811,12.7));
#767=DIRECTION('',(1.,0.,0.));
#768=DIRECTION('',(0.,0.,-1.));
#769=AXIS2_PLACEMENT_3D('',#766,#767,#768);
#770=PLANE('',#769);
#771=DIRECTION('',(0.,-1.,0.));
#772=VECTOR('',#771,1.);
#773=CARTESIAN_POINT('',(19.1389,12.0504714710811,-12.7));
#774=LINE('',#773,#772);
#775=CARTESIAN_POINT('',(19.1389,12.0504714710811,-12.7));
#776=VERTEX_POINT('',#775);
#777=EDGE_CURVE('E309',#745,#776,#774,.T.);
#778=ORIENTED_EDGE('',*,*,#777,.T.);
#779=DIRECTION('',(0.,0.,-1.));
#780=VECTOR('',#779,1.);
#781=CARTESIAN_POINT('',(19.1389,12.0504714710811,12.7));
#782=LINE('',#781,#780);
#783=CARTESIAN_POINT('',(19.1389,12.0504714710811,12.7));
#784=VERTEX_POINT('',#783);
#785=EDGE_CURVE('E325',#784,#776,#782,.T.);
#786=ORIENTED_EDGE('',*,*,#785,.F.);
#787=DIRECTION('',(0.,-1.,0.));
#788=VECTOR('',#787,1.);
#789=CARTESIAN_POINT('',(19.1389,12.0504714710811,12.7));
#790=LINE('',#789,#788);
#791=EDGE_CURVE('E457',#753,#784,#790,.T.);
#792=ORIENTED_EDGE('',*,*,#791,.F.);
#793=ORIENTED_EDGE('',*,*,#754,.T.);
#794=EDGE_LOOP('',(#778,#786,#792,#793));
#795=FACE_BOUND('',#794,.T.);
#796=ADVANCED_FACE('F568',(#795),#770,.F.);
#797=CARTESIAN_POINT('',(22.1361,8.69949999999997,12.7));
#798=DIRECTION('',(0.,0.,-1.));
#799=DIRECTION('',(-1.,0.,0.));
#800=AXIS2_PLACEMENT_3D('',#797,#798,#799);
#801=CYLINDRICAL_SURFACE('',#800,4.4958);
#802=CARTESIAN_POINT('',(22.1361,8.69949999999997,-12.7));
#803=DIRECTION('',(0.,0.,1.));
#804=DIRECTION('',(1.,0.,0.));
#805=AXIS2_PLACEMENT_3D('',#802,#803,#804);
#806=CIRCLE('',#805,4.4958);
#807=CARTESIAN_POINT('',(19.1389,5.34852852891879,-12.7));
#808=VERTEX_POINT('',#807);
#809=EDGE_CURVE('E311',#776,#808,#806,.T.);
#810=ORIENTED_EDGE('',*,*,#809,.T.);
#811=DIRECTION('',(0.,0.,-1.));
#812=VECTOR('',#811,1.);
#813=CARTESIAN_POINT('',(19.1389,5.34852852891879,12.7));
#814=LINE('',#813,#812);
#815=CARTESIAN_POINT('',(19.1389,5.34852852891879,12.7));
#816=VERTEX_POINT('',#815);
#817=EDGE_CURVE('E322',#816,#808,#814,.T.);
#818=ORIENTED_EDGE('',*,*,#817,.F.);
#819=CARTESIAN_POINT('',(22.1361,8.69949999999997,12.7));
#820=DIRECTION('',(0.,0.,1.));
#821=DIRECTION('',(1.,0.,0.));
#822=AXIS2_PLACEMENT_3D('',#819,#820,#821);
#823=CIRCLE('',#822,4.4958);
#824=EDGE_CURVE('E459',#784,#816,#823,.T.);
#825=ORIENTED_EDGE('',*,*,#824,.F.);
#826=ORIENTED_EDGE('',*,*,#785,.T.);
#827=EDGE_LOOP('',(#810,#818,#825,#826));
#828=FACE_BOUND('',#827,.T.);
#829=ADVANCED_FACE('F465',(#828),#801,.T.);
#830=CARTESIAN_POINT('',(19.1389,1.49860000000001,12.7));
#831=DIRECTION('',(1.,0.,0.));
#832=DIRECTION('',(0.,0.,-1.));
#833=AXIS2_PLACEMENT_3D('',#830,#831,#832);
#834=PLANE('',#833);
#835=DIRECTION('',(0.,-1.,0.));
#836=VECTOR('',#835,1.);
#837=CARTESIAN_POINT('',(19.1389,1.49860000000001,-12.7));
#838=LINE('',#837,#836);
#839=CARTESIAN_POINT('',(19.1389,1.49860000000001,-12.7));
#840=VERTEX_POINT('',#839);
#841=EDGE_CURVE('E313',#808,#840,#838,.T.);
#842=ORIENTED_EDGE('',*,*,#841,.T.);
#843=DIRECTION('',(0.,0.,-1.));
#844=VECTOR('',#843,1.);
#845=CARTESIAN_POINT('',(19.1389,1.49860000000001,12.7));
#846=LINE('',#845,#844);
#847=CARTESIAN_POINT('',(19.1389,1.49860000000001,12.7));
#848=VERTEX_POINT('',#847);
#849=EDGE_CURVE('E252',#848,#840,#846,.T.);
#850=ORIENTED_EDGE('',*,*,#849,.F.);
#851=DIRECTION('',(0.,-1.,0.));
#852=VECTOR('',#851,1.);
#853=CARTESIAN_POINT('',(19.1389,1.49860000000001,12.7));
#854=LINE('',#853,#852);
#855=EDGE_CURVE('E243',#816,#848,#854,.T.);
#856=ORIENTED_EDGE('',*,*,#855,.F.);
#857=ORIENTED_EDGE('',*,*,#817,.T.);
#858=EDGE_LOOP('',(#842,#850,#856,#857));
#859=FACE_BOUND('',#858,.T.);
#860=ADVANCED_FACE('F469',(#859),#834,.F.);
#861=CARTESIAN_POINT('',(-19.1389,1.4986,12.7));
#862=DIRECTION('',(0.,-1.,0.));
#863=DIRECTION('',(1.,0.,0.));
#864=AXIS2_PLACEMENT_3D('',#861,#862,#863);
#865=PLANE('',#864);
#866=DIRECTION('',(-1.,0.,0.));
#867=VECTOR('',#866,1.);
#868=CARTESIAN_POINT('',(-19.1389,1.4986,-12.7));
#869=LINE('',#868,#867);
#870=CARTESIAN_POINT('',(-19.1389,1.4986,-12.7));
#871=VERTEX_POINT('',#870);
#872=EDGE_CURVE('E251',#840,#871,#869,.T.);
#873=ORIENTED_EDGE('',*,*,#872,.T.);
#874=DIRECTION('',(0.,0.,-1.));
#875=VECTOR('',#874,1.);
#876=CARTESIAN_POINT('',(-19.1389,1.4986,12.7));
#877=LINE('',#876,#875);
#878=CARTESIAN_POINT('',(-19.1389,1.4986,12.7));
#879=VERTEX_POINT('',#878);
#880=EDGE_CURVE('E248',#879,#871,#877,.T.);
#881=ORIENTED_EDGE('',*,*,#880,.F.);
#882=DIRECTION('',(-1.,0.,0.));
#883=VECTOR('',#882,1.);
#884=CARTESIAN_POINT('',(-19.1389,1.4986,12.7));
#885=LINE('',#884,#883);
#886=EDGE_CURVE('E237',#848,#879,#885,.T.);
#887=ORIENTED_EDGE('',*,*,#886,.F.);
#888=ORIENTED_EDGE('',*,*,#849,.T.);
#889=EDGE_LOOP('',(#873,#881,#887,#888));
#890=FACE_BOUND('',#889,.T.);
#891=ADVANCED_FACE('F249',(#890),#865,.F.);
#892=CARTESIAN_POINT('',(-19.1389,5.34852852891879,12.7));
#893=DIRECTION('',(-1.,0.,0.));
#894=DIRECTION('',(0.,-1.,0.));
#895=AXIS2_PLACEMENT_3D('',#892,#893,#894);
#896=PLANE('',#895);
#897=DIRECTION('',(0.,1.,0.));
#898=VECTOR('',#897,1.);
#899=CARTESIAN_POINT('',(-19.1389,5.34852852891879,-12.7));
#900=LINE('',#899,#898);
#901=CARTESIAN_POINT('',(-19.1389,5.34852852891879,-12.7));
#902=VERTEX_POINT('',#901);
#903=EDGE_CURVE('E141',#871,#902,#900,.T.);
#904=ORIENTED_EDGE('',*,*,#903,.T.);
#905=DIRECTION('',(0.,0.,-1.));
#906=VECTOR('',#905,1.);
#907=CARTESIAN_POINT('',(-19.1389,5.34852852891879,12.7));
#908=LINE('',#907,#906);
#909=CARTESIAN_POINT('',(-19.1389,5.34852852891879,12.7));
#910=VERTEX_POINT('',#909);
#911=EDGE_CURVE('E253',#910,#902,#908,.T.);
#912=ORIENTED_EDGE('',*,*,#911,.F.);
#913=DIRECTION('',(0.,1.,0.));
#914=VECTOR('',#913,1.);
#915=CARTESIAN_POINT('',(-19.1389,5.34852852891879,12.7));
#916=LINE('',#915,#914);
#917=EDGE_CURVE('E241',#879,#910,#916,.T.);
#918=ORIENTED_EDGE('',*,*,#917,.F.);
#919=ORIENTED_EDGE('',*,*,#880,.T.);
#920=EDGE_LOOP('',(#904,#912,#918,#919));
#921=FACE_BOUND('',#920,.T.);
#922=ADVANCED_FACE('F255',(#921),#896,.F.);
#923=CARTESIAN_POINT('',(-22.1361,8.69949999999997,12.7));
#924=DIRECTION('',(0.,0.,-1.));
#925=DIRECTION('',(-1.,0.,0.));
#926=AXIS2_PLACEMENT_3D('',#923,#924,#925);
#927=CYLINDRICAL_SURFACE('',#926,4.4958);
#928=CARTESIAN_POINT('',(-22.1361,8.69949999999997,-12.7));
#929=DIRECTION('',(0.,0.,1.));
#930=DIRECTION('',(1.,0.,0.));
#931=AXIS2_PLACEMENT_3D('',#928,#929,#930);
#932=CIRCLE('',#931,4.4958);
#933=EDGE_CURVE('E147',#902,#29,#932,.T.);
#934=ORIENTED_EDGE('',*,*,#933,.T.);
#935=ORIENTED_EDGE('',*,*,#54,.F.);
#936=CARTESIAN_POINT('',(-22.1361,8.69949999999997,12.7));
#937=DIRECTION('',(0.,0.,1.));
#938=DIRECTION('',(1.,0.,0.));
#939=AXIS2_PLACEMENT_3D('',#936,#937,#938);
#940=CIRCLE('',#939,4.4958);
#941=EDGE_CURVE('E48',#910,#47,#940,.T.);
#942=ORIENTED_EDGE('',*,*,#941,.F.);
#943=ORIENTED_EDGE('',*,*,#911,.T.);
#944=EDGE_LOOP('',(#934,#935,#942,#943));
#945=FACE_BOUND('',#944,.T.);
#946=ADVANCED_FACE('F473',(#945),#927,.T.);
#947=CARTESIAN_POINT('',(-22.1361,8.69949999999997,12.7));
#948=DIRECTION('',(0.,0.,1.));
#949=DIRECTION('',(1.,0.,0.));
#950=AXIS2_PLACEMENT_3D('',#947,#948,#949);
#951=PLANE('',#950);
#952=ORIENTED_EDGE('',*,*,#48,.T.);
#953=ORIENTED_EDGE('',*,*,#84,.T.);
#954=ORIENTED_EDGE('',*,*,#115,.T.);
#955=ORIENTED_EDGE('',*,*,#146,.T.);
#956=ORIENTED_EDGE('',*,*,#177,.T.);
#957=ORIENTED_EDGE('',*,*,#210,.T.);
#958=ORIENTED_EDGE('',*,*,#241,.T.);
#959=ORIENTED_EDGE('',*,*,#274,.T.);
#960=ORIENTED_EDGE('',*,*,#305,.T.);
#961=ORIENTED_EDGE('',*,*,#338,.T.);
#962=ORIENTED_EDGE('',*,*,#369,.T.);
#963=ORIENTED_EDGE('',*,*,#402,.T.);
#964=CARTESIAN_POINT('',(-19.1389,-1.4986,12.7));
#965=DIRECTION('',(0.,0.,-1.));
#966=DIRECTION('',(-1.,0.,0.));
#967=AXIS2_PLACEMENT_3D('',#964,#965,#966);
#968=CIRCLE('',#967,1.4986);
#969=CARTESIAN_POINT('',(-20.6375,-1.4986,12.7));
#970=VERTEX_POINT('',#969);
#971=EDGE_CURVE('E1297',#970,#394,#968,.T.);
#972=ORIENTED_EDGE('',*,*,#971,.F.);
#973=DIRECTION('',(0.,1.,0.));
#974=VECTOR('',#973,1.);
#975=CARTESIAN_POINT('',(-20.6375,-6.10384865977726,12.7));
#976=LINE('',#975,#974);
#977=CARTESIAN_POINT('',(-20.6375,-6.10384865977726,12.7));
#978=VERTEX_POINT('',#977);
#979=EDGE_CURVE('E1300',#978,#970,#976,.T.);
#980=ORIENTED_EDGE('',*,*,#979,.F.);
#981=CARTESIAN_POINT('',(-22.1361,-8.69949999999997,12.7));
#982=DIRECTION('',(0.,0.,1.));
#983=DIRECTION('',(1.,0.,0.));
#984=AXIS2_PLACEMENT_3D('',#981,#982,#983);
#985=CIRCLE('',#984,2.9972);
#986=CARTESIAN_POINT('',(-20.6375,-11.2951513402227,12.7));
#987=VERTEX_POINT('',#986);
#988=EDGE_CURVE('E1303',#987,#978,#985,.T.);
#989=ORIENTED_EDGE('',*,*,#988,.F.);
#990=DIRECTION('',(0.,1.,0.));
#991=VECTOR('',#990,1.);
#992=CARTESIAN_POINT('',(-20.6375,-19.1389,12.7));
#993=LINE('',#992,#991);
#994=CARTESIAN_POINT('',(-20.6375,-19.1389,12.7));
#995=VERTEX_POINT('',#994);
#996=EDGE_CURVE('E1306',#995,#987,#993,.T.);
#997=ORIENTED_EDGE('',*,*,#996,.F.);
#998=CARTESIAN_POINT('',(-19.1389,-19.1389,12.7));
#999=DIRECTION('',(0.,0.,-1.));
#1000=DIRECTION('',(-1.,0.,0.));
#1001=AXIS2_PLACEMENT_3D('',#998,#999,#1000);
#1002=CIRCLE('',#1001,1.4986);
#1003=CARTESIAN_POINT('',(-19.1389,-20.6375,12.7));
#1004=VERTEX_POINT('',#1003);
#1005=EDGE_CURVE('E1309',#1004,#995,#1002,.T.);
#1006=ORIENTED_EDGE('',*,*,#1005,.F.);
#1007=DIRECTION('',(-1.,0.,0.));
#1008=VECTOR('',#1007,1.);
#1009=CARTESIAN_POINT('',(-19.1389,-20.6375,12.7));
#1010=LINE('',#1009,#1008);
#1011=CARTESIAN_POINT('',(-12.6111,-20.6375,12.7));
#1012=VERTEX_POINT('',#1011);
#1013=EDGE_CURVE('E1312',#1012,#1004,#1010,.T.);
#1014=ORIENTED_EDGE('',*,*,#1013,.F.);
#1015=CARTESIAN_POINT('',(-12.6111,-19.1389,12.7));
#1016=DIRECTION('',(0.,0.,-1.));
#1017=DIRECTION('',(-1.,0.,0.));
#1018=AXIS2_PLACEMENT_3D('',#1015,#1016,#1017);
#1019=CIRCLE('',#1018,1.4986);
#1020=CARTESIAN_POINT('',(-11.1125,-19.1389,12.7));
#1021=VERTEX_POINT('',#1020);
#1022=EDGE_CURVE('E1315',#1021,#1012,#1019,.T.);
#1023=ORIENTED_EDGE('',*,*,#1022,.F.);
#1024=DIRECTION('',(0.,-1.,0.));
#1025=VECTOR('',#1024,1.);
#1026=CARTESIAN_POINT('',(-11.1125,-19.1389,12.7));
#1027=LINE('',#1026,#1025);
#1028=CARTESIAN_POINT('',(-11.1125,-14.2875,12.7));
#1029=VERTEX_POINT('',#1028);
#1030=EDGE_CURVE('E1318',#1029,#1021,#1027,.T.);
#1031=ORIENTED_EDGE('',*,*,#1030,.F.);
#1032=DIRECTION('',(1.,0.,0.));
#1033=VECTOR('',#1032,1.);
#1034=CARTESIAN_POINT('',(-12.6111,-14.2875,12.7));
#1035=LINE('',#1034,#1033);
#1036=CARTESIAN_POINT('',(-12.6111,-14.2875,12.7));
#1037=VERTEX_POINT('',#1036);
#1038=EDGE_CURVE('E1321',#1037,#1029,#1035,.T.);
#1039=ORIENTED_EDGE('',*,*,#1038,.F.);
#1040=DIRECTION('',(0.,1.,0.));
#1041=VECTOR('',#1040,1.);
#1042=CARTESIAN_POINT('',(-12.6111,-19.1389,12.7));
#1043=LINE('',#1042,#1041);
#1044=CARTESIAN_POINT('',(-12.6111,-19.1389,12.7));
#1045=VERTEX_POINT('',#1044);
#1046=EDGE_CURVE('E1323',#1045,#1037,#1043,.T.);
#1047=ORIENTED_EDGE('',*,*,#1046,.F.);
#1048=DIRECTION('',(1.,0.,0.));
#1049=VECTOR('',#1048,1.);
#1050=CARTESIAN_POINT('',(-19.1389,-19.1389,12.7));
#1051=LINE('',#1050,#1049);
#1052=CARTESIAN_POINT('',(-19.1389,-19.1389,12.7));
#1053=VERTEX_POINT('',#1052);
#1054=EDGE_CURVE('E939',#1053,#1045,#1051,.T.);
#1055=ORIENTED_EDGE('',*,*,#1054,.F.);
#1056=DIRECTION('',(0.,-1.,0.));
#1057=VECTOR('',#1056,1.);
#1058=CARTESIAN_POINT('',(-19.1389,-19.1389,12.7));
#1059=LINE('',#1058,#1057);
#1060=CARTESIAN_POINT('',(-19.1389,-12.0504714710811,12.7));
#1061=VERTEX_POINT('',#1060);
#1062=EDGE_CURVE('E929',#1061,#1053,#1059,.T.);
#1063=ORIENTED_EDGE('',*,*,#1062,.F.);
#1064=CARTESIAN_POINT('',(-22.1361,-8.69949999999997,12.7));
#1065=DIRECTION('',(0.,0.,-1.));
#1066=DIRECTION('',(1.,0.,0.));
#1067=AXIS2_PLACEMENT_3D('',#1064,#1065,#1066);
#1068=CIRCLE('',#1067,4.4958);
#1069=CARTESIAN_POINT('',(-19.1389,-5.34852852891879,12.7));
#1070=VERTEX_POINT('',#1069);
#1071=EDGE_CURVE('E932',#1070,#1061,#1068,.T.);
#1072=ORIENTED_EDGE('',*,*,#1071,.F.);
#1073=DIRECTION('',(0.,-1.,0.));
#1074=VECTOR('',#1073,1.);
#1075=CARTESIAN_POINT('',(-19.1389,-5.34852852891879,12.7));
#1076=LINE('',#1075,#1074);
#1077=CARTESIAN_POINT('',(-19.1389,-1.4986,12.7));
#1078=VERTEX_POINT('',#1077);
#1079=EDGE_CURVE('E1247',#1078,#1070,#1076,.T.);
#1080=ORIENTED_EDGE('',*,*,#1079,.F.);
#1081=DIRECTION('',(-1.,0.,0.));
#1082=VECTOR('',#1081,1.);
#1083=CARTESIAN_POINT('',(-19.1389,-1.4986,12.7));
#1084=LINE('',#1083,#1082);
#1085=CARTESIAN_POINT('',(19.1389,-1.49860000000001,12.7));
#1086=VERTEX_POINT('',#1085);
#1087=EDGE_CURVE('E1251',#1086,#1078,#1084,.T.);
#1088=ORIENTED_EDGE('',*,*,#1087,.F.);
#1089=DIRECTION('',(0.,1.,0.));
#1090=VECTOR('',#1089,1.);
#1091=CARTESIAN_POINT('',(19.1389,-1.49860000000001,12.7));
#1092=LINE('',#1091,#1090);
#1093=CARTESIAN_POINT('',(19.1389,-5.34852852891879,12.7));
#1094=VERTEX_POINT('',#1093);
#1095=EDGE_CURVE('E1253',#1094,#1086,#1092,.T.);
#1096=ORIENTED_EDGE('',*,*,#1095,.F.);
#1097=CARTESIAN_POINT('',(22.1361,-8.69949999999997,12.7));
#1098=DIRECTION('',(0.,0.,-1.));
#1099=DIRECTION('',(1.,0.,0.));
#1100=AXIS2_PLACEMENT_3D('',#1097,#1098,#1099);
#1101=CIRCLE('',#1100,4.4958);
#1102=CARTESIAN_POINT('',(19.1389,-12.0504714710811,12.7));
#1103=VERTEX_POINT('',#1102);
#1104=EDGE_CURVE('E1258',#1103,#1094,#1101,.T.);
#1105=ORIENTED_EDGE('',*,*,#1104,.F.);
#1106=DIRECTION('',(0.,1.,0.));
#1107=VECTOR('',#1106,1.);
#1108=CARTESIAN_POINT('',(19.1389,-12.0504714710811,12.7));
#1109=LINE('',#1108,#1107);
#1110=CARTESIAN_POINT('',(19.1389,-19.1389,12.7));
#1111=VERTEX_POINT('',#1110);
#1112=EDGE_CURVE('E1261',#1111,#1103,#1109,.T.);
#1113=ORIENTED_EDGE('',*,*,#1112,.F.);
#1114=DIRECTION('',(1.,0.,0.));
#1115=VECTOR('',#1114,1.);
#1116=CARTESIAN_POINT('',(19.1389,-19.1389,12.7));
#1117=LINE('',#1116,#1115);
#1118=CARTESIAN_POINT('',(12.6111,-19.1389,12.7));
#1119=VERTEX_POINT('',#1118);
#1120=EDGE_CURVE('E1264',#1119,#1111,#1117,.T.);
#1121=ORIENTED_EDGE('',*,*,#1120,.F.);
#1122=DIRECTION('',(0.,-1.,0.));
#1123=VECTOR('',#1122,1.);
#1124=CARTESIAN_POINT('',(12.6111,-19.1389,12.7));
#1125=LINE('',#1124,#1123);
#1126=CARTESIAN_POINT('',(12.6111,-14.2875,12.7));
#1127=VERTEX_POINT('',#1126);
#1128=EDGE_CURVE('E1267',#1127,#1119,#1125,.T.);
#1129=ORIENTED_EDGE('',*,*,#1128,.F.);
#1130=DIRECTION('',(1.,0.,0.));
#1131=VECTOR('',#1130,1.);
#1132=CARTESIAN_POINT('',(11.1125,-14.2875,12.7));
#1133=LINE('',#1132,#1131);
#1134=CARTESIAN_POINT('',(11.1125,-14.2875,12.7));
#1135=VERTEX_POINT('',#1134);
#1136=EDGE_CURVE('E1270',#1135,#1127,#1133,.T.);
#1137=ORIENTED_EDGE('',*,*,#1136,.F.);
#1138=DIRECTION('',(0.,1.,0.));
#1139=VECTOR('',#1138,1.);
#1140=CARTESIAN_POINT('',(11.1125,-19.1389,12.7));
#1141=LINE('',#1140,#1139);
#1142=CARTESIAN_POINT('',(11.1125,-19.1389,12.7));
#1143=VERTEX_POINT('',#1142);
#1144=EDGE_CURVE('E1273',#1143,#1135,#1141,.T.);
#1145=ORIENTED_EDGE('',*,*,#1144,.F.);
#1146=CARTESIAN_POINT('',(12.6111,-19.1389,12.7));
#1147=DIRECTION('',(0.,0.,-1.));
#1148=DIRECTION('',(-1.,0.,0.));
#1149=AXIS2_PLACEMENT_3D('',#1146,#1147,#1148);
#1150=CIRCLE('',#1149,1.4986);
#1151=CARTESIAN_POINT('',(12.6111,-20.6375,12.7));
#1152=VERTEX_POINT('',#1151);
#1153=EDGE_CURVE('E1276',#1152,#1143,#1150,.T.);
#1154=ORIENTED_EDGE('',*,*,#1153,.F.);
#1155=DIRECTION('',(-1.,0.,0.));
#1156=VECTOR('',#1155,1.);
#1157=CARTESIAN_POINT('',(19.1389,-20.6375,12.7));
#1158=LINE('',#1157,#1156);
#1159=CARTESIAN_POINT('',(19.1389,-20.6375,12.7));
#1160=VERTEX_POINT('',#1159);
#1161=EDGE_CURVE('E1279',#1160,#1152,#1158,.T.);
#1162=ORIENTED_EDGE('',*,*,#1161,.F.);
#1163=CARTESIAN_POINT('',(19.1389,-19.1389,12.7));
#1164=DIRECTION('',(0.,0.,-1.));
#1165=DIRECTION('',(-1.,0.,0.));
#1166=AXIS2_PLACEMENT_3D('',#1163,#1164,#1165);
#1167=CIRCLE('',#1166,1.4986);
#1168=CARTESIAN_POINT('',(20.6375,-19.1389,12.7));
#1169=VERTEX_POINT('',#1168);
#1170=EDGE_CURVE('E1282',#1169,#1160,#1167,.T.);
#1171=ORIENTED_EDGE('',*,*,#1170,.F.);
#1172=DIRECTION('',(0.,-1.,0.));
#1173=VECTOR('',#1172,1.);
#1174=CARTESIAN_POINT('',(20.6375,-11.2951513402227,12.7));
#1175=LINE('',#1174,#1173);
#1176=CARTESIAN_POINT('',(20.6375,-11.2951513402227,12.7));
#1177=VERTEX_POINT('',#1176);
#1178=EDGE_CURVE('E1285',#1177,#1169,#1175,.T.);
#1179=ORIENTED_EDGE('',*,*,#1178,.F.);
#1180=CARTESIAN_POINT('',(22.1361,-8.69949999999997,12.7));
#1181=DIRECTION('',(0.,0.,1.));
#1182=DIRECTION('',(1.,0.,0.));
#1183=AXIS2_PLACEMENT_3D('',#1180,#1181,#1182);
#1184=CIRCLE('',#1183,2.9972);
#1185=CARTESIAN_POINT('',(20.6375,-6.10384865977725,12.7));
#1186=VERTEX_POINT('',#1185);
#1187=EDGE_CURVE('E1288',#1186,#1177,#1184,.T.);
#1188=ORIENTED_EDGE('',*,*,#1187,.F.);
#1189=DIRECTION('',(0.,-1.,0.));
#1190=VECTOR('',#1189,1.);
#1191=CARTESIAN_POINT('',(20.6375,-1.49860000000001,12.7));
#1192=LINE('',#1191,#1190);
#1193=CARTESIAN_POINT('',(20.6375,-1.49860000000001,12.7));
#1194=VERTEX_POINT('',#1193);
#1195=EDGE_CURVE('E1291',#1194,#1186,#1192,.T.);
#1196=ORIENTED_EDGE('',*,*,#1195,.F.);
#1197=CARTESIAN_POINT('',(19.1389,-1.49860000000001,12.7));
#1198=DIRECTION('',(0.,0.,-1.));
#1199=DIRECTION('',(-1.,0.,0.));
#1200=AXIS2_PLACEMENT_3D('',#1197,#1198,#1199);
#1201=CIRCLE('',#1200,1.4986);
#1202=EDGE_CURVE('E1294',#438,#1194,#1201,.T.);
#1203=ORIENTED_EDGE('',*,*,#1202,.F.);
#1204=ORIENTED_EDGE('',*,*,#439,.T.);
#1205=ORIENTED_EDGE('',*,*,#475,.T.);
#1206=ORIENTED_EDGE('',*,*,#508,.T.);
#1207=ORIENTED_EDGE('',*,*,#539,.T.);
#1208=ORIENTED_EDGE('',*,*,#572,.T.);
#1209=ORIENTED_EDGE('',*,*,#603,.T.);
#1210=ORIENTED_EDGE('',*,*,#636,.T.);
#1211=ORIENTED_EDGE('',*,*,#667,.T.);
#1212=ORIENTED_EDGE('',*,*,#698,.T.);
#1213=ORIENTED_EDGE('',*,*,#729,.T.);
#1214=ORIENTED_EDGE('',*,*,#760,.T.);
#1215=ORIENTED_EDGE('',*,*,#791,.T.);
#1216=ORIENTED_EDGE('',*,*,#824,.T.);
#1217=ORIENTED_EDGE('',*,*,#855,.T.);
#1218=ORIENTED_EDGE('',*,*,#886,.T.);
#1219=ORIENTED_EDGE('',*,*,#917,.T.);
#1220=ORIENTED_EDGE('',*,*,#941,.T.);
#1221=EDGE_LOOP('',(#952,#953,#954,#955,#956,#957,#958,#959,#960,#961,#962,#963,#972,#980,#989,
#997,#1006,#1014,#1023,#1031,#1039,#1047,#1055,#1063,#1072,#1080,#1088,#1096,#1105,#1113,#1121,
#1129,#1137,#1145,#1154,#1162,#1171,#1179,#1188,#1196,#1203,#1204,#1205,#1206,#1207,#1208,#1209,
#1210,#1211,#1212,#1213,#1214,#1215,#1216,#1217,#1218,#1219,#1220));
#1222=FACE_BOUND('',#1221,.T.);
#1223=ADVANCED_FACE('F239',(#1222),#951,.T.);
#1224=CARTESIAN_POINT('',(-22.1361,8.69949999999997,-12.7));
#1225=DIRECTION('',(0.,0.,1.));
#1226=DIRECTION('',(1.,0.,0.));
#1227=AXIS2_PLACEMENT_3D('',#1224,#1225,#1226);
#1228=PLANE('',#1227);
#1229=ORIENTED_EDGE('',*,*,#32,.F.);
#1230=ORIENTED_EDGE('',*,*,#933,.F.);
#1231=ORIENTED_EDGE('',*,*,#903,.F.);
#1232=ORIENTED_EDGE('',*,*,#872,.F.);
#1233=ORIENTED_EDGE('',*,*,#841,.F.);
#1234=ORIENTED_EDGE('',*,*,#809,.F.);
#1235=ORIENTED_EDGE('',*,*,#777,.F.);
#1236=ORIENTED_EDGE('',*,*,#746,.F.);
#1237=ORIENTED_EDGE('',*,*,#715,.F.);
#1238=ORIENTED_EDGE('',*,*,#684,.F.);
#1239=ORIENTED_EDGE('',*,*,#653,.F.);
#1240=ORIENTED_EDGE('',*,*,#621,.F.);
#1241=ORIENTED_EDGE('',*,*,#589,.F.);
#1242=ORIENTED_EDGE('',*,*,#557,.F.);
#1243=ORIENTED_EDGE('',*,*,#525,.F.);
#1244=ORIENTED_EDGE('',*,*,#493,.F.);
#1245=ORIENTED_EDGE('',*,*,#461,.F.);
#1246=ORIENTED_EDGE('',*,*,#422,.F.);
#1247=CARTESIAN_POINT('',(19.1389,-1.49860000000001,-12.7));
#1248=DIRECTION('',(0.,0.,-1.));
#1249=DIRECTION('',(-1.,0.,0.));
#1250=AXIS2_PLACEMENT_3D('',#1247,#1248,#1249);
#1251=CIRCLE('',#1250,1.4986);
#1252=CARTESIAN_POINT('',(20.6375,-1.49860000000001,-12.7));
#1253=VERTEX_POINT('',#1252);
#1254=EDGE_CURVE('E1082',#419,#1253,#1251,.T.);
#1255=ORIENTED_EDGE('',*,*,#1254,.T.);
#1256=DIRECTION('',(0.,-1.,0.));
#1257=VECTOR('',#1256,1.);
#1258=CARTESIAN_POINT('',(20.6375,-1.49860000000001,-12.7));
#1259=LINE('',#1258,#1257);
#1260=CARTESIAN_POINT('',(20.6375,-6.10384865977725,-12.7));
#1261=VERTEX_POINT('',#1260);
#1262=EDGE_CURVE('E1079',#1253,#1261,#1259,.T.);
#1263=ORIENTED_EDGE('',*,*,#1262,.T.);
#1264=CARTESIAN_POINT('',(22.1361,-8.69949999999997,-12.7));
#1265=DIRECTION('',(0.,0.,1.));
#1266=DIRECTION('',(1.,0.,0.));
#1267=AXIS2_PLACEMENT_3D('',#1264,#1265,#1266);
#1268=CIRCLE('',#1267,2.9972);
#1269=CARTESIAN_POINT('',(20.6375,-11.2951513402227,-12.7));
#1270=VERTEX_POINT('',#1269);
#1271=EDGE_CURVE('E1076',#1261,#1270,#1268,.T.);
#1272=ORIENTED_EDGE('',*,*,#1271,.T.);
#1273=DIRECTION('',(0.,-1.,0.));
#1274=VECTOR('',#1273,1.);
#1275=CARTESIAN_POINT('',(20.6375,-11.2951513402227,-12.7));
#1276=LINE('',#1275,#1274);
#1277=CARTESIAN_POINT('',(20.6375,-19.1389,-12.7));
#1278=VERTEX_POINT('',#1277);
#1279=EDGE_CURVE('E1073',#1270,#1278,#1276,.T.);
#1280=ORIENTED_EDGE('',*,*,#1279,.T.);
#1281=CARTESIAN_POINT('',(19.1389,-19.1389,-12.7));
#1282=DIRECTION('',(0.,0.,-1.));
#1283=DIRECTION('',(-1.,0.,0.));
#1284=AXIS2_PLACEMENT_3D('',#1281,#1282,#1283);
#1285=CIRCLE('',#1284,1.4986);
#1286=CARTESIAN_POINT('',(19.1389,-20.6375,-12.7));
#1287=VERTEX_POINT('',#1286);
#1288=EDGE_CURVE('E1070',#1278,#1287,#1285,.T.);
#1289=ORIENTED_EDGE('',*,*,#1288,.T.);
#1290=DIRECTION('',(-1.,0.,0.));
#1291=VECTOR('',#1290,1.);
#1292=CARTESIAN_POINT('',(19.1389,-20.6375,-12.7));
#1293=LINE('',#1292,#1291);
#1294=CARTESIAN_POINT('',(12.6111,-20.6375,-12.7));
#1295=VERTEX_POINT('',#1294);
#1296=EDGE_CURVE('E1067',#1287,#1295,#1293,.T.);
#1297=ORIENTED_EDGE('',*,*,#1296,.T.);
#1298=CARTESIAN_POINT('',(12.6111,-19.1389,-12.7));
#1299=DIRECTION('',(0.,0.,-1.));
#1300=DIRECTION('',(-1.,0.,0.));
#1301=AXIS2_PLACEMENT_3D('',#1298,#1299,#1300);
#1302=CIRCLE('',#1301,1.4986);
#1303=CARTESIAN_POINT('',(11.1125,-19.1389,-12.7));
#1304=VERTEX_POINT('',#1303);
#1305=EDGE_CURVE('E1064',#1295,#1304,#1302,.T.);
#1306=ORIENTED_EDGE('',*,*,#1305,.T.);
#1307=DIRECTION('',(0.,1.,0.));
#1308=VECTOR('',#1307,1.);
#1309=CARTESIAN_POINT('',(11.1125,-19.1389,-12.7));
#1310=LINE('',#1309,#1308);
#1311=CARTESIAN_POINT('',(11.1125,-14.2875,-12.7));
#1312=VERTEX_POINT('',#1311);
#1313=EDGE_CURVE('E1061',#1304,#1312,#1310,.T.);
#1314=ORIENTED_EDGE('',*,*,#1313,.T.);
#1315=DIRECTION('',(1.,0.,0.));
#1316=VECTOR('',#1315,1.);
#1317=CARTESIAN_POINT('',(11.1125,-14.2875,-12.7));
#1318=LINE('',#1317,#1316);
#1319=CARTESIAN_POINT('',(12.6111,-14.2875,-12.7));
#1320=VERTEX_POINT('',#1319);
#1321=EDGE_CURVE('E1058',#1312,#1320,#1318,.T.);
#1322=ORIENTED_EDGE('',*,*,#1321,.T.);
#1323=DIRECTION('',(0.,-1.,0.));
#1324=VECTOR('',#1323,1.);
#1325=CARTESIAN_POINT('',(12.6111,-19.1389,-12.7));
#1326=LINE('',#1325,#1324);
#1327=CARTESIAN_POINT('',(12.6111,-19.1389,-12.7));
#1328=VERTEX_POINT('',#1327);
#1329=EDGE_CURVE('E1055',#1320,#1328,#1326,.T.);
#1330=ORIENTED_EDGE('',*,*,#1329,.T.);
#1331=DIRECTION('',(1.,0.,0.));
#1332=VECTOR('',#1331,1.);
#1333=CARTESIAN_POINT('',(19.1389,-19.1389,-12.7));
#1334=LINE('',#1333,#1332);
#1335=CARTESIAN_POINT('',(19.1389,-19.1389,-12.7));
#1336=VERTEX_POINT('',#1335);
#1337=EDGE_CURVE('E1052',#1328,#1336,#1334,.T.);
#1338=ORIENTED_EDGE('',*,*,#1337,.T.);
#1339=DIRECTION('',(0.,1.,0.));
#1340=VECTOR('',#1339,1.);
#1341=CARTESIAN_POINT('',(19.1389,-12.0504714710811,-12.7));
#1342=LINE('',#1341,#1340);
#1343=CARTESIAN_POINT('',(19.1389,-12.0504714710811,-12.7));
#1344=VERTEX_POINT('',#1343);
#1345=EDGE_CURVE('E1049',#1336,#1344,#1342,.T.);
#1346=ORIENTED_EDGE('',*,*,#1345,.T.);
#1347=CARTESIAN_POINT('',(22.1361,-8.69949999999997,-12.7));
#1348=DIRECTION('',(0.,0.,-1.));
#1349=DIRECTION('',(1.,0.,0.));
#1350=AXIS2_PLACEMENT_3D('',#1347,#1348,#1349);
#1351=CIRCLE('',#1350,4.4958);
#1352=CARTESIAN_POINT('',(19.1389,-5.34852852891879,-12.7));
#1353=VERTEX_POINT('',#1352);
#1354=EDGE_CURVE('E1046',#1344,#1353,#1351,.T.);
#1355=ORIENTED_EDGE('',*,*,#1354,.T.);
#1356=DIRECTION('',(0.,1.,0.));
#1357=VECTOR('',#1356,1.);
#1358=CARTESIAN_POINT('',(19.1389,-1.49860000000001,-12.7));
#1359=LINE('',#1358,#1357);
#1360=CARTESIAN_POINT('',(19.1389,-1.49860000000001,-12.7));
#1361=VERTEX_POINT('',#1360);
#1362=EDGE_CURVE('E1043',#1353,#1361,#1359,.T.);
#1363=ORIENTED_EDGE('',*,*,#1362,.T.);
#1364=DIRECTION('',(-1.,0.,0.));
#1365=VECTOR('',#1364,1.);
#1366=CARTESIAN_POINT('',(-19.1389,-1.4986,-12.7));
#1367=LINE('',#1366,#1365);
#1368=CARTESIAN_POINT('',(-19.1389,-1.4986,-12.7));
#1369=VERTEX_POINT('',#1368);
#1370=EDGE_CURVE('E1038',#1361,#1369,#1367,.T.);
#1371=ORIENTED_EDGE('',*,*,#1370,.T.);
#1372=DIRECTION('',(0.,-1.,0.));
#1373=VECTOR('',#1372,1.);
#1374=CARTESIAN_POINT('',(-19.1389,-5.34852852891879,-12.7));
#1375=LINE('',#1374,#1373);
#1376=CARTESIAN_POINT('',(-19.1389,-5.34852852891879,-12.7));
#1377=VERTEX_POINT('',#1376);
#1378=EDGE_CURVE('E1036',#1369,#1377,#1375,.T.);
#1379=ORIENTED_EDGE('',*,*,#1378,.T.);
#1380=CARTESIAN_POINT('',(-22.1361,-8.69949999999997,-12.7));
#1381=DIRECTION('',(0.,0.,-1.));
#1382=DIRECTION('',(1.,0.,0.));
#1383=AXIS2_PLACEMENT_3D('',#1380,#1381,#1382);
#1384=CIRCLE('',#1383,4.4958);
#1385=CARTESIAN_POINT('',(-19.1389,-12.0504714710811,-12.7));
#1386=VERTEX_POINT('',#1385);
#1387=EDGE_CURVE('E1027',#1377,#1386,#1384,.T.);
#1388=ORIENTED_EDGE('',*,*,#1387,.T.);
#1389=DIRECTION('',(0.,-1.,0.));
#1390=VECTOR('',#1389,1.);
#1391=CARTESIAN_POINT('',(-19.1389,-19.1389,-12.7));
#1392=LINE('',#1391,#1390);
#1393=CARTESIAN_POINT('',(-19.1389,-19.1389,-12.7));
#1394=VERTEX_POINT('',#1393);
#1395=EDGE_CURVE('E1032',#1386,#1394,#1392,.T.);
#1396=ORIENTED_EDGE('',*,*,#1395,.T.);
#1397=DIRECTION('',(1.,0.,0.));
#1398=VECTOR('',#1397,1.);
#1399=CARTESIAN_POINT('',(-19.1389,-19.1389,-12.7));
#1400=LINE('',#1399,#1398);
#1401=CARTESIAN_POINT('',(-12.6111,-19.1389,-12.7));
#1402=VERTEX_POINT('',#1401);
#1403=EDGE_CURVE('E917',#1394,#1402,#1400,.T.);
#1404=ORIENTED_EDGE('',*,*,#1403,.T.);
#1405=DIRECTION('',(0.,1.,0.));
#1406=VECTOR('',#1405,1.);
#1407=CARTESIAN_POINT('',(-12.6111,-19.1389,-12.7));
#1408=LINE('',#1407,#1406);
#1409=CARTESIAN_POINT('',(-12.6111,-14.2875,-12.7));
#1410=VERTEX_POINT('',#1409);
#1411=EDGE_CURVE('E930',#1402,#1410,#1408,.T.);
#1412=ORIENTED_EDGE('',*,*,#1411,.T.);
#1413=DIRECTION('',(1.,0.,0.));
#1414=VECTOR('',#1413,1.);
#1415=CARTESIAN_POINT('',(-12.6111,-14.2875,-12.7));
#1416=LINE('',#1415,#1414);
#1417=CARTESIAN_POINT('',(-11.1125,-14.2875,-12.7));
#1418=VERTEX_POINT('',#1417);
#1419=EDGE_CURVE('E934',#1410,#1418,#1416,.T.);
#1420=ORIENTED_EDGE('',*,*,#1419,.T.);
#1421=DIRECTION('',(0.,-1.,0.));
#1422=VECTOR('',#1421,1.);
#1423=CARTESIAN_POINT('',(-11.1125,-19.1389,-12.7));
#1424=LINE('',#1423,#1422);
#1425=CARTESIAN_POINT('',(-11.1125,-19.1389,-12.7));
#1426=VERTEX_POINT('',#1425);
#1427=EDGE_CURVE('E1106',#1418,#1426,#1424,.T.);
#1428=ORIENTED_EDGE('',*,*,#1427,.T.);
#1429=CARTESIAN_POINT('',(-12.6111,-19.1389,-12.7));
#1430=DIRECTION('',(0.,0.,-1.));
#1431=DIRECTION('',(-1.,0.,0.));
#1432=AXIS2_PLACEMENT_3D('',#1429,#1430,#1431);
#1433=CIRCLE('',#1432,1.4986);
#1434=CARTESIAN_POINT('',(-12.6111,-20.6375,-12.7));
#1435=VERTEX_POINT('',#1434);
#1436=EDGE_CURVE('E1103',#1426,#1435,#1433,.T.);
#1437=ORIENTED_EDGE('',*,*,#1436,.T.);
#1438=DIRECTION('',(-1.,0.,0.));
#1439=VECTOR('',#1438,1.);
#1440=CARTESIAN_POINT('',(-19.1389,-20.6375,-12.7));
#1441=LINE('',#1440,#1439);
#1442=CARTESIAN_POINT('',(-19.1389,-20.6375,-12.7));
#1443=VERTEX_POINT('',#1442);
#1444=EDGE_CURVE('E1100',#1435,#1443,#1441,.T.);
#1445=ORIENTED_EDGE('',*,*,#1444,.T.);
#1446=CARTESIAN_POINT('',(-19.1389,-19.1389,-12.7));
#1447=DIRECTION('',(0.,0.,-1.));
#1448=DIRECTION('',(-1.,0.,0.));
#1449=AXIS2_PLACEMENT_3D('',#1446,#1447,#1448);
#1450=CIRCLE('',#1449,1.4986);
#1451=CARTESIAN_POINT('',(-20.6375,-19.1389,-12.7));
#1452=VERTEX_POINT('',#1451);
#1453=EDGE_CURVE('E1097',#1443,#1452,#1450,.T.);
#1454=ORIENTED_EDGE('',*,*,#1453,.T.);
#1455=DIRECTION('',(0.,1.,0.));
#1456=VECTOR('',#1455,1.);
#1457=CARTESIAN_POINT('',(-20.6375,-19.1389,-12.7));
#1458=LINE('',#1457,#1456);
#1459=CARTESIAN_POINT('',(-20.6375,-11.2951513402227,-12.7));
#1460=VERTEX_POINT('',#1459);
#1461=EDGE_CURVE('E1094',#1452,#1460,#1458,.T.);
#1462=ORIENTED_EDGE('',*,*,#1461,.T.);
#1463=CARTESIAN_POINT('',(-22.1361,-8.69949999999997,-12.7));
#1464=DIRECTION('',(0.,0.,1.));
#1465=DIRECTION('',(1.,0.,0.));
#1466=AXIS2_PLACEMENT_3D('',#1463,#1464,#1465);
#1467=CIRCLE('',#1466,2.9972);
#1468=CARTESIAN_POINT('',(-20.6375,-6.10384865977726,-12.7));
#1469=VERTEX_POINT('',#1468);
#1470=EDGE_CURVE('E1091',#1460,#1469,#1467,.T.);
#1471=ORIENTED_EDGE('',*,*,#1470,.T.);
#1472=DIRECTION('',(0.,1.,0.));
#1473=VECTOR('',#1472,1.);
#1474=CARTESIAN_POINT('',(-20.6375,-6.10384865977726,-12.7));
#1475=LINE('',#1474,#1473);
#1476=CARTESIAN_POINT('',(-20.6375,-1.4986,-12.7));
#1477=VERTEX_POINT('',#1476);
#1478=EDGE_CURVE('E1088',#1469,#1477,#1475,.T.);
#1479=ORIENTED_EDGE('',*,*,#1478,.T.);
#1480=CARTESIAN_POINT('',(-19.1389,-1.4986,-12.7));
#1481=DIRECTION('',(0.,0.,-1.));
#1482=DIRECTION('',(-1.,0.,0.));
#1483=AXIS2_PLACEMENT_3D('',#1480,#1481,#1482);
#1484=CIRCLE('',#1483,1.4986);
#1485=EDGE_CURVE('E1085',#1477,#386,#1484,.T.);
#1486=ORIENTED_EDGE('',*,*,#1485,.T.);
#1487=ORIENTED_EDGE('',*,*,#387,.F.);
#1488=ORIENTED_EDGE('',*,*,#355,.F.);
#1489=ORIENTED_EDGE('',*,*,#323,.F.);
#1490=ORIENTED_EDGE('',*,*,#291,.F.);
#1491=ORIENTED_EDGE('',*,*,#259,.F.);
#1492=ORIENTED_EDGE('',*,*,#227,.F.);
#1493=ORIENTED_EDGE('',*,*,#195,.F.);
#1494=ORIENTED_EDGE('',*,*,#163,.F.);
#1495=ORIENTED_EDGE('',*,*,#132,.F.);
#1496=ORIENTED_EDGE('',*,*,#101,.F.);
#1497=ORIENTED_EDGE('',*,*,#70,.F.);
#1498=EDGE_LOOP('',(#1229,#1230,#1231,#1232,#1233,#1234,#1235,#1236,#1237,#1238,#1239,#1240,
#1241,#1242,#1243,#1244,#1245,#1246,#1255,#1263,#1272,#1280,#1289,#1297,#1306,#1314,#1322,#1330,
#1338,#1346,#1355,#1363,#1371,#1379,#1388,#1396,#1404,#1412,#1420,#1428,#1437,#1445,#1454,#1462,
#1471,#1479,#1486,#1487,#1488,#1489,#1490,#1491,#1492,#1493,#1494,#1495,#1496,#1497));
#1499=FACE_BOUND('',#1498,.T.);
#1500=ADVANCED_FACE('F403',(#1499),#1228,.F.);
#1501=CARTESIAN_POINT('',(-19.1389,-19.1389,12.7));
#1502=DIRECTION('',(1.,0.,0.));
#1503=DIRECTION('',(0.,0.,-1.));
#1504=AXIS2_PLACEMENT_3D('',#1501,#1502,#1503);
#1505=PLANE('',#1504);
#1506=ORIENTED_EDGE('',*,*,#1395,.F.);
#1507=DIRECTION('',(0.,0.,-1.));
#1508=VECTOR('',#1507,1.);
#1509=CARTESIAN_POINT('',(-19.1389,-12.0504714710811,12.7));
#1510=LINE('',#1509,#1508);
#1511=EDGE_CURVE('E265',#1061,#1386,#1510,.T.);
#1512=ORIENTED_EDGE('',*,*,#1511,.F.);
#1513=ORIENTED_EDGE('',*,*,#1062,.T.);
#1514=DIRECTION('',(0.,0.,-1.));
#1515=VECTOR('',#1514,1.);
#1516=CARTESIAN_POINT('',(-19.1389,-19.1389,12.7));
#1517=LINE('',#1516,#1515);
#1518=EDGE_CURVE('E920',#1053,#1394,#1517,.T.);
#1519=ORIENTED_EDGE('',*,*,#1518,.T.);
#1520=EDGE_LOOP('',(#1506,#1512,#1513,#1519));
#1521=FACE_BOUND('',#1520,.T.);
#1522=ADVANCED_FACE('F621',(#1521),#1505,.T.);
#1523=CARTESIAN_POINT('',(-22.1361,-8.69949999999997,12.7));
#1524=DIRECTION('',(0.,0.,-1.));
#1525=DIRECTION('',(-1.,0.,0.));
#1526=AXIS2_PLACEMENT_3D('',#1523,#1524,#1525);
#1527=CYLINDRICAL_SURFACE('',#1526,4.4958);
#1528=ORIENTED_EDGE('',*,*,#1387,.F.);
#1529=DIRECTION('',(0.,0.,-1.));
#1530=VECTOR('',#1529,1.);
#1531=CARTESIAN_POINT('',(-19.1389,-5.34852852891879,12.7));
#1532=LINE('',#1531,#1530);
#1533=EDGE_CURVE('E1013',#1070,#1377,#1532,.T.);
#1534=ORIENTED_EDGE('',*,*,#1533,.F.);
#1535=ORIENTED_EDGE('',*,*,#1071,.T.);
#1536=ORIENTED_EDGE('',*,*,#1511,.T.);
#1537=EDGE_LOOP('',(#1528,#1534,#1535,#1536));
#1538=FACE_BOUND('',#1537,.T.);
#1539=ADVANCED_FACE('F629',(#1538),#1527,.T.);
#1540=CARTESIAN_POINT('',(-19.1389,-5.34852852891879,12.7));
#1541=DIRECTION('',(1.,0.,0.));
#1542=DIRECTION('',(0.,1.,0.));
#1543=AXIS2_PLACEMENT_3D('',#1540,#1541,#1542);
#1544=PLANE('',#1543);
#1545=ORIENTED_EDGE('',*,*,#1378,.F.);
#1546=DIRECTION('',(0.,0.,-1.));
#1547=VECTOR('',#1546,1.);
#1548=CARTESIAN_POINT('',(-19.1389,-1.4986,12.7));
#1549=LINE('',#1548,#1547);
#1550=EDGE_CURVE('E1010',#1078,#1369,#1549,.T.);
#1551=ORIENTED_EDGE('',*,*,#1550,.F.);
#1552=ORIENTED_EDGE('',*,*,#1079,.T.);
#1553=ORIENTED_EDGE('',*,*,#1533,.T.);
#1554=EDGE_LOOP('',(#1545,#1551,#1552,#1553));
#1555=FACE_BOUND('',#1554,.T.);
#1556=ADVANCED_FACE('F639',(#1555),#1544,.T.);
#1557=CARTESIAN_POINT('',(-19.1389,-1.4986,12.7));
#1558=DIRECTION('',(0.,-1.,0.));
#1559=DIRECTION('',(1.,0.,0.));
#1560=AXIS2_PLACEMENT_3D('',#1557,#1558,#1559);
#1561=PLANE('',#1560);
#1562=ORIENTED_EDGE('',*,*,#1370,.F.);
#1563=DIRECTION('',(0.,0.,-1.));
#1564=VECTOR('',#1563,1.);
#1565=CARTESIAN_POINT('',(19.1389,-1.49860000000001,12.7));
#1566=LINE('',#1565,#1564);
#1567=EDGE_CURVE('E1007',#1086,#1361,#1566,.T.);
#1568=ORIENTED_EDGE('',*,*,#1567,.F.);
#1569=ORIENTED_EDGE('',*,*,#1087,.T.);
#1570=ORIENTED_EDGE('',*,*,#1550,.T.);
#1571=EDGE_LOOP('',(#1562,#1568,#1569,#1570));
#1572=FACE_BOUND('',#1571,.T.);
#1573=ADVANCED_FACE('F649',(#1572),#1561,.T.);
#1574=CARTESIAN_POINT('',(19.1389,-1.49860000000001,12.7));
#1575=DIRECTION('',(-1.,0.,0.));
#1576=DIRECTION('',(0.,0.,1.));
#1577=AXIS2_PLACEMENT_3D('',#1574,#1575,#1576);
#1578=PLANE('',#1577);
#1579=ORIENTED_EDGE('',*,*,#1362,.F.);
#1580=DIRECTION('',(0.,0.,-1.));
#1581=VECTOR('',#1580,1.);
#1582=CARTESIAN_POINT('',(19.1389,-5.34852852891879,12.7));
#1583=LINE('',#1582,#1581);
#1584=EDGE_CURVE('E1004',#1094,#1353,#1583,.T.);
#1585=ORIENTED_EDGE('',*,*,#1584,.F.);
#1586=ORIENTED_EDGE('',*,*,#1095,.T.);
#1587=ORIENTED_EDGE('',*,*,#1567,.T.);
#1588=EDGE_LOOP('',(#1579,#1585,#1586,#1587));
#1589=FACE_BOUND('',#1588,.T.);
#1590=ADVANCED_FACE('F659',(#1589),#1578,.T.);
#1591=CARTESIAN_POINT('',(22.1361,-8.69949999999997,12.7));
#1592=DIRECTION('',(0.,0.,-1.));
#1593=DIRECTION('',(-1.,0.,0.));
#1594=AXIS2_PLACEMENT_3D('',#1591,#1592,#1593);
#1595=CYLINDRICAL_SURFACE('',#1594,4.4958);
#1596=ORIENTED_EDGE('',*,*,#1354,.F.);
#1597=DIRECTION('',(0.,0.,-1.));
#1598=VECTOR('',#1597,1.);
#1599=CARTESIAN_POINT('',(19.1389,-12.0504714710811,12.7));
#1600=LINE('',#1599,#1598);
#1601=EDGE_CURVE('E1001',#1103,#1344,#1600,.T.);
#1602=ORIENTED_EDGE('',*,*,#1601,.F.);
#1603=ORIENTED_EDGE('',*,*,#1104,.T.);
#1604=ORIENTED_EDGE('',*,*,#1584,.T.);
#1605=EDGE_LOOP('',(#1596,#1602,#1603,#1604));
#1606=FACE_BOUND('',#1605,.T.);
#1607=ADVANCED_FACE('F669',(#1606),#1595,.T.);
#1608=CARTESIAN_POINT('',(19.1389,-12.0504714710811,12.7));
#1609=DIRECTION('',(-1.,0.,0.));
#1610=DIRECTION('',(0.,0.,1.));
#1611=AXIS2_PLACEMENT_3D('',#1608,#1609,#1610);
#1612=PLANE('',#1611);
#1613=ORIENTED_EDGE('',*,*,#1345,.F.);
#1614=DIRECTION('',(0.,0.,-1.));
#1615=VECTOR('',#1614,1.);
#1616=CARTESIAN_POINT('',(19.1389,-19.1389,12.7));
#1617=LINE('',#1616,#1615);
#1618=EDGE_CURVE('E998',#1111,#1336,#1617,.T.);
#1619=ORIENTED_EDGE('',*,*,#1618,.F.);
#1620=ORIENTED_EDGE('',*,*,#1112,.T.);
#1621=ORIENTED_EDGE('',*,*,#1601,.T.);
#1622=EDGE_LOOP('',(#1613,#1619,#1620,#1621));
#1623=FACE_BOUND('',#1622,.T.);
#1624=ADVANCED_FACE('F679',(#1623),#1612,.T.);
#1625=CARTESIAN_POINT('',(19.1389,-19.1389,12.7));
#1626=DIRECTION('',(0.,1.,0.));
#1627=DIRECTION('',(-1.,0.,0.));
#1628=AXIS2_PLACEMENT_3D('',#1625,#1626,#1627);
#1629=PLANE('',#1628);
#1630=ORIENTED_EDGE('',*,*,#1337,.F.);
#1631=DIRECTION('',(0.,0.,-1.));
#1632=VECTOR('',#1631,1.);
#1633=CARTESIAN_POINT('',(12.6111,-19.1389,12.7));
#1634=LINE('',#1633,#1632);
#1635=EDGE_CURVE('E995',#1119,#1328,#1634,.T.);
#1636=ORIENTED_EDGE('',*,*,#1635,.F.);
#1637=ORIENTED_EDGE('',*,*,#1120,.T.);
#1638=ORIENTED_EDGE('',*,*,#1618,.T.);
#1639=EDGE_LOOP('',(#1630,#1636,#1637,#1638));
#1640=FACE_BOUND('',#1639,.T.);
#1641=ADVANCED_FACE('F689',(#1640),#1629,.T.);
#1642=CARTESIAN_POINT('',(12.6111,-19.1389,12.7));
#1643=DIRECTION('',(1.,0.,0.));
#1644=DIRECTION('',(0.,0.,-1.));
#1645=AXIS2_PLACEMENT_3D('',#1642,#1643,#1644);
#1646=PLANE('',#1645);
#1647=ORIENTED_EDGE('',*,*,#1329,.F.);
#1648=DIRECTION('',(0.,0.,-1.));
#1649=VECTOR('',#1648,1.);
#1650=CARTESIAN_POINT('',(12.6111,-14.2875,12.7));
#1651=LINE('',#1650,#1649);
#1652=EDGE_CURVE('E992',#1127,#1320,#1651,.T.);
#1653=ORIENTED_EDGE('',*,*,#1652,.F.);
#1654=ORIENTED_EDGE('',*,*,#1128,.T.);
#1655=ORIENTED_EDGE('',*,*,#1635,.T.);
#1656=EDGE_LOOP('',(#1647,#1653,#1654,#1655));
#1657=FACE_BOUND('',#1656,.T.);
#1658=ADVANCED_FACE('F699',(#1657),#1646,.T.);
#1659=CARTESIAN_POINT('',(11.1125,-14.2875,12.7));
#1660=DIRECTION('',(0.,1.,0.));
#1661=DIRECTION('',(0.,0.,1.));
#1662=AXIS2_PLACEMENT_3D('',#1659,#1660,#1661);
#1663=PLANE('',#1662);
#1664=ORIENTED_EDGE('',*,*,#1321,.F.);
#1665=DIRECTION('',(0.,0.,-1.));
#1666=VECTOR('',#1665,1.);
#1667=CARTESIAN_POINT('',(11.1125,-14.2875,12.7));
#1668=LINE('',#1667,#1666);
#1669=EDGE_CURVE('E989',#1135,#1312,#1668,.T.);
#1670=ORIENTED_EDGE('',*,*,#1669,.F.);
#1671=ORIENTED_EDGE('',*,*,#1136,.T.);
#1672=ORIENTED_EDGE('',*,*,#1652,.T.);
#1673=EDGE_LOOP('',(#1664,#1670,#1671,#1672));
#1674=FACE_BOUND('',#1673,.T.);
#1675=ADVANCED_FACE('F709',(#1674),#1663,.T.);
#1676=CARTESIAN_POINT('',(11.1125,-19.1389,12.7));
#1677=DIRECTION('',(-1.,0.,0.));
#1678=DIRECTION('',(0.,-1.,0.));
#1679=AXIS2_PLACEMENT_3D('',#1676,#1677,#1678);
#1680=PLANE('',#1679);
#1681=ORIENTED_EDGE('',*,*,#1313,.F.);
#1682=DIRECTION('',(0.,0.,-1.));
#1683=VECTOR('',#1682,1.);
#1684=CARTESIAN_POINT('',(11.1125,-19.1389,12.7));
#1685=LINE('',#1684,#1683);
#1686=EDGE_CURVE('E986',#1143,#1304,#1685,.T.);
#1687=ORIENTED_EDGE('',*,*,#1686,.F.);
#1688=ORIENTED_EDGE('',*,*,#1144,.T.);
#1689=ORIENTED_EDGE('',*,*,#1669,.T.);
#1690=EDGE_LOOP('',(#1681,#1687,#1688,#1689));
#1691=FACE_BOUND('',#1690,.T.);
#1692=ADVANCED_FACE('F719',(#1691),#1680,.T.);
#1693=CARTESIAN_POINT('',(12.6111,-19.1389,12.7));
#1694=DIRECTION('',(0.,0.,-1.));
#1695=DIRECTION('',(-1.,0.,0.));
#1696=AXIS2_PLACEMENT_3D('',#1693,#1694,#1695);
#1697=CYLINDRICAL_SURFACE('',#1696,1.4986);
#1698=ORIENTED_EDGE('',*,*,#1305,.F.);
#1699=DIRECTION('',(0.,0.,-1.));
#1700=VECTOR('',#1699,1.);
#1701=CARTESIAN_POINT('',(12.6111,-20.6375,12.7));
#1702=LINE('',#1701,#1700);
#1703=EDGE_CURVE('E983',#1152,#1295,#1702,.T.);
#1704=ORIENTED_EDGE('',*,*,#1703,.F.);
#1705=ORIENTED_EDGE('',*,*,#1153,.T.);
#1706=ORIENTED_EDGE('',*,*,#1686,.T.);
#1707=EDGE_LOOP('',(#1698,#1704,#1705,#1706));
#1708=FACE_BOUND('',#1707,.T.);
#1709=ADVANCED_FACE('F729',(#1708),#1697,.T.);
#1710=CARTESIAN_POINT('',(19.1389,-20.6375,12.7));
#1711=DIRECTION('',(0.,-1.,0.));
#1712=DIRECTION('',(1.,0.,0.));
#1713=AXIS2_PLACEMENT_3D('',#1710,#1711,#1712);
#1714=PLANE('',#1713);
#1715=ORIENTED_EDGE('',*,*,#1296,.F.);
#1716=DIRECTION('',(0.,0.,-1.));
#1717=VECTOR('',#1716,1.);
#1718=CARTESIAN_POINT('',(19.1389,-20.6375,12.7));
#1719=LINE('',#1718,#1717);
#1720=EDGE_CURVE('E980',#1160,#1287,#1719,.T.);
#1721=ORIENTED_EDGE('',*,*,#1720,.F.);
#1722=ORIENTED_EDGE('',*,*,#1161,.T.);
#1723=ORIENTED_EDGE('',*,*,#1703,.T.);
#1724=EDGE_LOOP('',(#1715,#1721,#1722,#1723));
#1725=FACE_BOUND('',#1724,.T.);
#1726=ADVANCED_FACE('F739',(#1725),#1714,.T.);
#1727=CARTESIAN_POINT('',(19.1389,-19.1389,12.7));
#1728=DIRECTION('',(0.,0.,-1.));
#1729=DIRECTION('',(-1.,0.,0.));
#1730=AXIS2_PLACEMENT_3D('',#1727,#1728,#1729);
#1731=CYLINDRICAL_SURFACE('',#1730,1.4986);
#1732=ORIENTED_EDGE('',*,*,#1288,.F.);
#1733=DIRECTION('',(0.,0.,-1.));
#1734=VECTOR('',#1733,1.);
#1735=CARTESIAN_POINT('',(20.6375,-19.1389,12.7));
#1736=LINE('',#1735,#1734);
#1737=EDGE_CURVE('E977',#1169,#1278,#1736,.T.);
#1738=ORIENTED_EDGE('',*,*,#1737,.F.);
#1739=ORIENTED_EDGE('',*,*,#1170,.T.);
#1740=ORIENTED_EDGE('',*,*,#1720,.T.);
#1741=EDGE_LOOP('',(#1732,#1738,#1739,#1740));
#1742=FACE_BOUND('',#1741,.T.);
#1743=ADVANCED_FACE('F749',(#1742),#1731,.T.);
#1744=CARTESIAN_POINT('',(20.6375,-11.2951513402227,12.7));
#1745=DIRECTION('',(1.,0.,0.));
#1746=DIRECTION('',(0.,1.,0.));
#1747=AXIS2_PLACEMENT_3D('',#1744,#1745,#1746);
#1748=PLANE('',#1747);
#1749=ORIENTED_EDGE('',*,*,#1279,.F.);
#1750=DIRECTION('',(0.,0.,-1.));
#1751=VECTOR('',#1750,1.);
#1752=CARTESIAN_POINT('',(20.6375,-11.2951513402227,12.7));
#1753=LINE('',#1752,#1751);
#1754=EDGE_CURVE('E974',#1177,#1270,#1753,.T.);
#1755=ORIENTED_EDGE('',*,*,#1754,.F.);
#1756=ORIENTED_EDGE('',*,*,#1178,.T.);
#1757=ORIENTED_EDGE('',*,*,#1737,.T.);
#1758=EDGE_LOOP('',(#1749,#1755,#1756,#1757));
#1759=FACE_BOUND('',#1758,.T.);
#1760=ADVANCED_FACE('F759',(#1759),#1748,.T.);
#1761=CARTESIAN_POINT('',(22.1361,-8.69949999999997,12.7));
#1762=DIRECTION('',(0.,0.,-1.));
#1763=DIRECTION('',(-1.,0.,0.));
#1764=AXIS2_PLACEMENT_3D('',#1761,#1762,#1763);
#1765=CYLINDRICAL_SURFACE('',#1764,2.9972);
#1766=ORIENTED_EDGE('',*,*,#1271,.F.);
#1767=DIRECTION('',(0.,0.,-1.));
#1768=VECTOR('',#1767,1.);
#1769=CARTESIAN_POINT('',(20.6375,-6.10384865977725,12.7));
#1770=LINE('',#1769,#1768);
#1771=EDGE_CURVE('E971',#1186,#1261,#1770,.T.);
#1772=ORIENTED_EDGE('',*,*,#1771,.F.);
#1773=ORIENTED_EDGE('',*,*,#1187,.T.);
#1774=ORIENTED_EDGE('',*,*,#1754,.T.);
#1775=EDGE_LOOP('',(#1766,#1772,#1773,#1774));
#1776=FACE_BOUND('',#1775,.T.);
#1777=ADVANCED_FACE('F769',(#1776),#1765,.F.);
#1778=CARTESIAN_POINT('',(20.6375,-1.49860000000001,12.7));
#1779=DIRECTION('',(1.,0.,0.));
#1780=DIRECTION('',(0.,0.,-1.));
#1781=AXIS2_PLACEMENT_3D('',#1778,#1779,#1780);
#1782=PLANE('',#1781);
#1783=ORIENTED_EDGE('',*,*,#1262,.F.);
#1784=DIRECTION('',(0.,0.,-1.));
#1785=VECTOR('',#1784,1.);
#1786=CARTESIAN_POINT('',(20.6375,-1.49860000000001,12.7));
#1787=LINE('',#1786,#1785);
#1788=EDGE_CURVE('E968',#1194,#1253,#1787,.T.);
#1789=ORIENTED_EDGE('',*,*,#1788,.F.);
#1790=ORIENTED_EDGE('',*,*,#1195,.T.);
#1791=ORIENTED_EDGE('',*,*,#1771,.T.);
#1792=EDGE_LOOP('',(#1783,#1789,#1790,#1791));
#1793=FACE_BOUND('',#1792,.T.);
#1794=ADVANCED_FACE('F779',(#1793),#1782,.T.);
#1795=CARTESIAN_POINT('',(19.1389,-1.49860000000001,12.7));
#1796=DIRECTION('',(0.,0.,-1.));
#1797=DIRECTION('',(-1.,0.,0.));
#1798=AXIS2_PLACEMENT_3D('',#1795,#1796,#1797);
#1799=CYLINDRICAL_SURFACE('',#1798,1.4986);
#1800=ORIENTED_EDGE('',*,*,#1254,.F.);
#1801=ORIENTED_EDGE('',*,*,#445,.F.);
#1802=ORIENTED_EDGE('',*,*,#1202,.T.);
#1803=ORIENTED_EDGE('',*,*,#1788,.T.);
#1804=EDGE_LOOP('',(#1800,#1801,#1802,#1803));
#1805=FACE_BOUND('',#1804,.T.);
#1806=ADVANCED_FACE('F789',(#1805),#1799,.T.);
#1807=CARTESIAN_POINT('',(-19.1389,-1.4986,12.7));
#1808=DIRECTION('',(0.,0.,-1.));
#1809=DIRECTION('',(-1.,0.,0.));
#1810=AXIS2_PLACEMENT_3D('',#1807,#1808,#1809);
#1811=CYLINDRICAL_SURFACE('',#1810,1.4986);
#1812=ORIENTED_EDGE('',*,*,#1485,.F.);
#1813=DIRECTION('',(0.,0.,-1.));
#1814=VECTOR('',#1813,1.);
#1815=CARTESIAN_POINT('',(-20.6375,-1.4986,12.7));
#1816=LINE('',#1815,#1814);
#1817=EDGE_CURVE('E965',#970,#1477,#1816,.T.);
#1818=ORIENTED_EDGE('',*,*,#1817,.F.);
#1819=ORIENTED_EDGE('',*,*,#971,.T.);
#1820=ORIENTED_EDGE('',*,*,#395,.T.);
#1821=EDGE_LOOP('',(#1812,#1818,#1819,#1820));
#1822=FACE_BOUND('',#1821,.T.);
#1823=ADVANCED_FACE('F799',(#1822),#1811,.T.);
#1824=CARTESIAN_POINT('',(-20.6375,-6.10384865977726,12.7));
#1825=DIRECTION('',(-1.,0.,0.));
#1826=DIRECTION('',(0.,0.,1.));
#1827=AXIS2_PLACEMENT_3D('',#1824,#1825,#1826);
#1828=PLANE('',#1827);
#1829=ORIENTED_EDGE('',*,*,#1478,.F.);
#1830=DIRECTION('',(0.,0.,-1.));
#1831=VECTOR('',#1830,1.);
#1832=CARTESIAN_POINT('',(-20.6375,-6.10384865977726,12.7));
#1833=LINE('',#1832,#1831);
#1834=EDGE_CURVE('E962',#978,#1469,#1833,.T.);
#1835=ORIENTED_EDGE('',*,*,#1834,.F.);
#1836=ORIENTED_EDGE('',*,*,#979,.T.);
#1837=ORIENTED_EDGE('',*,*,#1817,.T.);
#1838=EDGE_LOOP('',(#1829,#1835,#1836,#1837));
#1839=FACE_BOUND('',#1838,.T.);
#1840=ADVANCED_FACE('F809',(#1839),#1828,.T.);
#1841=CARTESIAN_POINT('',(-22.1361,-8.69949999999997,12.7));
#1842=DIRECTION('',(0.,0.,-1.));
#1843=DIRECTION('',(-1.,0.,0.));
#1844=AXIS2_PLACEMENT_3D('',#1841,#1842,#1843);
#1845=CYLINDRICAL_SURFACE('',#1844,2.9972);
#1846=ORIENTED_EDGE('',*,*,#1470,.F.);
#1847=DIRECTION('',(0.,0.,-1.));
#1848=VECTOR('',#1847,1.);
#1849=CARTESIAN_POINT('',(-20.6375,-11.2951513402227,12.7));
#1850=LINE('',#1849,#1848);
#1851=EDGE_CURVE('E959',#987,#1460,#1850,.T.);
#1852=ORIENTED_EDGE('',*,*,#1851,.F.);
#1853=ORIENTED_EDGE('',*,*,#988,.T.);
#1854=ORIENTED_EDGE('',*,*,#1834,.T.);
#1855=EDGE_LOOP('',(#1846,#1852,#1853,#1854));
#1856=FACE_BOUND('',#1855,.T.);
#1857=ADVANCED_FACE('F819',(#1856),#1845,.F.);
#1858=CARTESIAN_POINT('',(-20.6375,-19.1389,12.7));
#1859=DIRECTION('',(-1.,0.,0.));
#1860=DIRECTION('',(0.,-1.,0.));
#1861=AXIS2_PLACEMENT_3D('',#1858,#1859,#1860);
#1862=PLANE('',#1861);
#1863=ORIENTED_EDGE('',*,*,#1461,.F.);
#1864=DIRECTION('',(0.,0.,-1.));
#1865=VECTOR('',#1864,1.);
#1866=CARTESIAN_POINT('',(-20.6375,-19.1389,12.7));
#1867=LINE('',#1866,#1865);
#1868=EDGE_CURVE('E956',#995,#1452,#1867,.T.);
#1869=ORIENTED_EDGE('',*,*,#1868,.F.);
#1870=ORIENTED_EDGE('',*,*,#996,.T.);
#1871=ORIENTED_EDGE('',*,*,#1851,.T.);
#1872=EDGE_LOOP('',(#1863,#1869,#1870,#1871));
#1873=FACE_BOUND('',#1872,.T.);
#1874=ADVANCED_FACE('F829',(#1873),#1862,.T.);
#1875=CARTESIAN_POINT('',(-19.1389,-19.1389,12.7));
#1876=DIRECTION('',(0.,0.,-1.));
#1877=DIRECTION('',(-1.,0.,0.));
#1878=AXIS2_PLACEMENT_3D('',#1875,#1876,#1877);
#1879=CYLINDRICAL_SURFACE('',#1878,1.4986);
#1880=ORIENTED_EDGE('',*,*,#1453,.F.);
#1881=DIRECTION('',(0.,0.,-1.));
#1882=VECTOR('',#1881,1.);
#1883=CARTESIAN_POINT('',(-19.1389,-20.6375,12.7));
#1884=LINE('',#1883,#1882);
#1885=EDGE_CURVE('E953',#1004,#1443,#1884,.T.);
#1886=ORIENTED_EDGE('',*,*,#1885,.F.);
#1887=ORIENTED_EDGE('',*,*,#1005,.T.);
#1888=ORIENTED_EDGE('',*,*,#1868,.T.);
#1889=EDGE_LOOP('',(#1880,#1886,#1887,#1888));
#1890=FACE_BOUND('',#1889,.T.);
#1891=ADVANCED_FACE('F839',(#1890),#1879,.T.);
#1892=CARTESIAN_POINT('',(-19.1389,-20.6375,12.7));
#1893=DIRECTION('',(0.,-1.,0.));
#1894=DIRECTION('',(0.,0.,-1.));
#1895=AXIS2_PLACEMENT_3D('',#1892,#1893,#1894);
#1896=PLANE('',#1895);
#1897=ORIENTED_EDGE('',*,*,#1444,.F.);
#1898=DIRECTION('',(0.,0.,-1.));
#1899=VECTOR('',#1898,1.);
#1900=CARTESIAN_POINT('',(-12.6111,-20.6375,12.7));
#1901=LINE('',#1900,#1899);
#1902=EDGE_CURVE('E950',#1012,#1435,#1901,.T.);
#1903=ORIENTED_EDGE('',*,*,#1902,.F.);
#1904=ORIENTED_EDGE('',*,*,#1013,.T.);
#1905=ORIENTED_EDGE('',*,*,#1885,.T.);
#1906=EDGE_LOOP('',(#1897,#1903,#1904,#1905));
#1907=FACE_BOUND('',#1906,.T.);
#1908=ADVANCED_FACE('F849',(#1907),#1896,.T.);
#1909=CARTESIAN_POINT('',(-12.6111,-19.1389,12.7));
#1910=DIRECTION('',(0.,0.,-1.));
#1911=DIRECTION('',(-1.,0.,0.));
#1912=AXIS2_PLACEMENT_3D('',#1909,#1910,#1911);
#1913=CYLINDRICAL_SURFACE('',#1912,1.4986);
#1914=ORIENTED_EDGE('',*,*,#1436,.F.);
#1915=DIRECTION('',(0.,0.,-1.));
#1916=VECTOR('',#1915,1.);
#1917=CARTESIAN_POINT('',(-11.1125,-19.1389,12.7));
#1918=LINE('',#1917,#1916);
#1919=EDGE_CURVE('E947',#1021,#1426,#1918,.T.);
#1920=ORIENTED_EDGE('',*,*,#1919,.F.);
#1921=ORIENTED_EDGE('',*,*,#1022,.T.);
#1922=ORIENTED_EDGE('',*,*,#1902,.T.);
#1923=EDGE_LOOP('',(#1914,#1920,#1921,#1922));
#1924=FACE_BOUND('',#1923,.T.);
#1925=ADVANCED_FACE('F859',(#1924),#1913,.T.);
#1926=CARTESIAN_POINT('',(-11.1125,-19.1389,12.7));
#1927=DIRECTION('',(1.,0.,0.));
#1928=DIRECTION('',(0.,1.,0.));
#1929=AXIS2_PLACEMENT_3D('',#1926,#1927,#1928);
#1930=PLANE('',#1929);
#1931=ORIENTED_EDGE('',*,*,#1427,.F.);
#1932=DIRECTION('',(0.,0.,-1.));
#1933=VECTOR('',#1932,1.);
#1934=CARTESIAN_POINT('',(-11.1125,-14.2875,12.7));
#1935=LINE('',#1934,#1933);
#1936=EDGE_CURVE('E944',#1029,#1418,#1935,.T.);
#1937=ORIENTED_EDGE('',*,*,#1936,.F.);
#1938=ORIENTED_EDGE('',*,*,#1030,.T.);
#1939=ORIENTED_EDGE('',*,*,#1919,.T.);
#1940=EDGE_LOOP('',(#1931,#1937,#1938,#1939));
#1941=FACE_BOUND('',#1940,.T.);
#1942=ADVANCED_FACE('F869',(#1941),#1930,.T.);
#1943=CARTESIAN_POINT('',(-12.6111,-14.2875,12.7));
#1944=DIRECTION('',(0.,1.,0.));
#1945=DIRECTION('',(0.,0.,1.));
#1946=AXIS2_PLACEMENT_3D('',#1943,#1944,#1945);
#1947=PLANE('',#1946);
#1948=ORIENTED_EDGE('',*,*,#1419,.F.);
#1949=DIRECTION('',(0.,0.,-1.));
#1950=VECTOR('',#1949,1.);
#1951=CARTESIAN_POINT('',(-12.6111,-14.2875,12.7));
#1952=LINE('',#1951,#1950);
#1953=EDGE_CURVE('E941',#1037,#1410,#1952,.T.);
#1954=ORIENTED_EDGE('',*,*,#1953,.F.);
#1955=ORIENTED_EDGE('',*,*,#1038,.T.);
#1956=ORIENTED_EDGE('',*,*,#1936,.T.);
#1957=EDGE_LOOP('',(#1948,#1954,#1955,#1956));
#1958=FACE_BOUND('',#1957,.T.);
#1959=ADVANCED_FACE('F879',(#1958),#1947,.T.);
#1960=CARTESIAN_POINT('',(-12.6111,-19.1389,12.7));
#1961=DIRECTION('',(-1.,0.,0.));
#1962=DIRECTION('',(0.,-1.,0.));
#1963=AXIS2_PLACEMENT_3D('',#1960,#1961,#1962);
#1964=PLANE('',#1963);
#1965=ORIENTED_EDGE('',*,*,#1411,.F.);
#1966=DIRECTION('',(0.,0.,-1.));
#1967=VECTOR('',#1966,1.);
#1968=CARTESIAN_POINT('',(-12.6111,-19.1389,12.7));
#1969=LINE('',#1968,#1967);
#1970=EDGE_CURVE('E924',#1045,#1402,#1969,.T.);
#1971=ORIENTED_EDGE('',*,*,#1970,.F.);
#1972=ORIENTED_EDGE('',*,*,#1046,.T.);
#1973=ORIENTED_EDGE('',*,*,#1953,.T.);
#1974=EDGE_LOOP('',(#1965,#1971,#1972,#1973));
#1975=FACE_BOUND('',#1974,.T.);
#1976=ADVANCED_FACE('F889',(#1975),#1964,.T.);
#1977=CARTESIAN_POINT('',(-19.1389,-19.1389,12.7));
#1978=DIRECTION('',(0.,1.,0.));
#1979=DIRECTION('',(0.,0.,1.));
#1980=AXIS2_PLACEMENT_3D('',#1977,#1978,#1979);
#1981=PLANE('',#1980);
#1982=ORIENTED_EDGE('',*,*,#1403,.F.);
#1983=ORIENTED_EDGE('',*,*,#1518,.F.);
#1984=ORIENTED_EDGE('',*,*,#1054,.T.);
#1985=ORIENTED_EDGE('',*,*,#1970,.T.);
#1986=EDGE_LOOP('',(#1982,#1983,#1984,#1985));
#1987=FACE_BOUND('',#1986,.T.);
#1988=ADVANCED_FACE('F899',(#1987),#1981,.T.);
#1989=CLOSED_SHELL('',(#58,#89,#120,#151,#182,#215,#246,#279,#310,#343,#374,#407,#449,#480,#513,
#544,#577,#608,#641,#672,#703,#734,#765,#796,#829,#860,#891,#922,#946,#1223,#1500,#1522,#1539,
#1556,#1573,#1590,#1607,#1624,#1641,#1658,#1675,#1692,#1709,#1726,#1743,#1760,#1777,#1794,#1806,
#1823,#1840,#1857,#1874,#1891,#1908,#1925,#1942,#1959,#1976,#1988));
#1990=MANIFOLD_SOLID_BREP('B2',#1989);
#1991=ADVANCED_BREP_SHAPE_REPRESENTATION('',(#18,#1990),#14);
#1992=SHAPE_DEFINITION_REPRESENTATION(#9,#1991);
ENDSEC;
END-ISO-10303-21;
